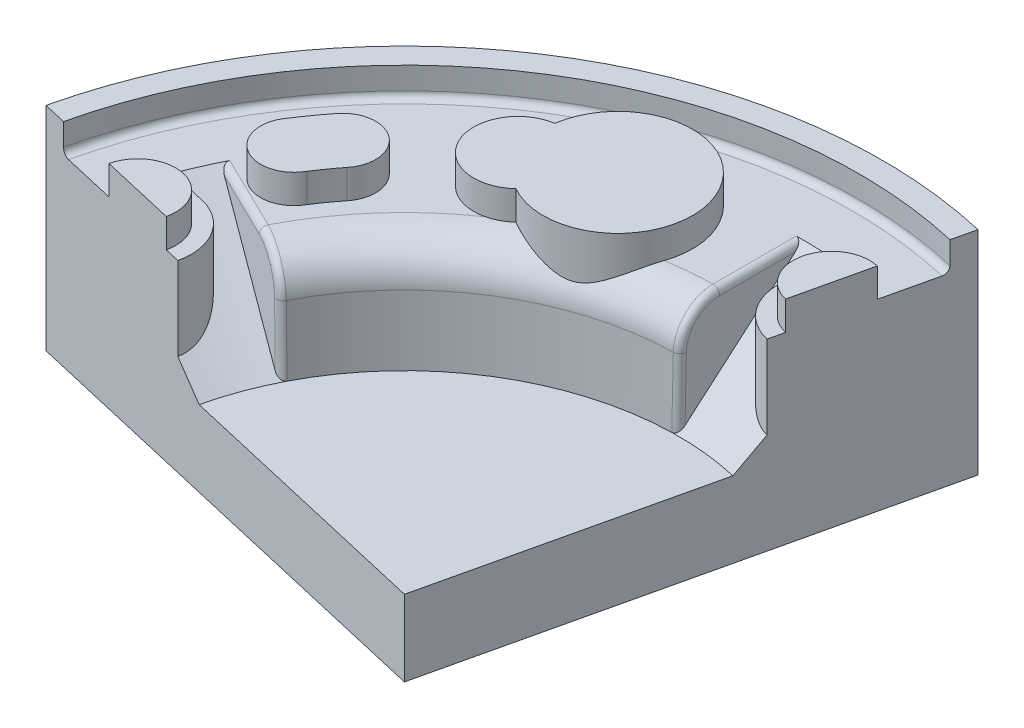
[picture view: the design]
ISO-10303-21;
HEADER;
FILE_DESCRIPTION(('STEP AP214'),'2;1');
FILE_NAME('part.step','',(''),(''),'','','');
FILE_SCHEMA(('AUTOMOTIVE_DESIGN { 1 0 10303 214 1 1 1 1 }'));
ENDSEC;
DATA;
#1=APPLICATION_CONTEXT('core data for automotive mechanical design processes');
#2=APPLICATION_PROTOCOL_DEFINITION('international standard','automotive_design',2000,#1);
#3=PRODUCT_CONTEXT('',#1,'mechanical');
#4=PRODUCT('Part','Part','',(#3));
#5=PRODUCT_RELATED_PRODUCT_CATEGORY('part','',(#4));
#6=PRODUCT_DEFINITION_FORMATION('','',#4);
#7=PRODUCT_DEFINITION_CONTEXT('part definition',#1,'design');
#8=PRODUCT_DEFINITION('design','',#6,#7);
#9=PRODUCT_DEFINITION_SHAPE('','',#8);
#10=(LENGTH_UNIT() NAMED_UNIT(*) SI_UNIT(.MILLI.,.METRE.));
#11=(NAMED_UNIT(*) PLANE_ANGLE_UNIT() SI_UNIT($,.RADIAN.));
#12=(NAMED_UNIT(*) SI_UNIT($,.STERADIAN.) SOLID_ANGLE_UNIT());
#13=UNCERTAINTY_MEASURE_WITH_UNIT(LENGTH_MEASURE(1.E-05),#10,'distance_accuracy_value','');
#14=(GEOMETRIC_REPRESENTATION_CONTEXT(3) GLOBAL_UNCERTAINTY_ASSIGNED_CONTEXT((#13)) GLOBAL_UNIT_ASSIGNED_CONTEXT((#10,
#11,#12)) REPRESENTATION_CONTEXT('',''));
#15=CARTESIAN_POINT('',(0.,0.,0.));
#16=DIRECTION('',(0.,0.,1.));
#17=DIRECTION('',(1.,0.,0.));
#18=AXIS2_PLACEMENT_3D('',#15,#16,#17);
#19=CARTESIAN_POINT('',(121.494829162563,21.9456,16.5481660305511));
#20=DIRECTION('',(0.,-1.,0.));
#21=DIRECTION('',(-0.224951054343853,0.,0.974370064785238));
#22=AXIS2_PLACEMENT_3D('',#19,#20,#21);
#23=PLANE('',#22);
#24=CARTESIAN_POINT('',(22.7978712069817,21.9456,30.2092155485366));
#25=DIRECTION('',(0.,-1.,0.));
#26=DIRECTION('',(0.974370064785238,0.,0.224951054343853));
#27=AXIS2_PLACEMENT_3D('',#24,#25,#26);
#28=CIRCLE('',#27,3.96956319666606);
#29=CARTESIAN_POINT('',(25.8758232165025,21.9456000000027,32.7159351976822));
#30=VERTEX_POINT('',#29);
#31=CARTESIAN_POINT('',(19.6209878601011,21.9456000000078,27.8291222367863));
#32=VERTEX_POINT('',#31);
#33=EDGE_CURVE('E584',#30,#32,#28,.F.);
#34=ORIENTED_EDGE('',*,*,#33,.F.);
#35=CARTESIAN_POINT('',(57.150000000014,21.9456000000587,57.1500000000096));
#36=DIRECTION('',(1.21401796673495E-12,-1.,8.47143766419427E-13));
#37=DIRECTION('',(0.974370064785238,1.37346864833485E-12,0.224951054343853));
#38=AXIS2_PLACEMENT_3D('',#35,#36,#37);
#39=CIRCLE('',#38,39.6874999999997);
#40=CARTESIAN_POINT('',(23.8652618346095,21.9456000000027,35.5346382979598));
#41=VERTEX_POINT('',#40);
#42=EDGE_CURVE('E581',#41,#30,#39,.T.);
#43=ORIENTED_EDGE('',*,*,#42,.F.);
#44=CARTESIAN_POINT('',(20.3938022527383,21.9456,33.5932808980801));
#45=DIRECTION('',(0.,-1.,0.));
#46=DIRECTION('',(-0.224951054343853,0.,0.974370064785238));
#47=AXIS2_PLACEMENT_3D('',#44,#45,#46);
#48=CIRCLE('',#47,3.97742381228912);
#49=CARTESIAN_POINT('',(17.2083142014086,21.9456000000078,31.2115659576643));
#50=VERTEX_POINT('',#49);
#51=EDGE_CURVE('E578',#50,#41,#48,.F.);
#52=ORIENTED_EDGE('',*,*,#51,.F.);
#53=CARTESIAN_POINT('',(57.1499999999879,21.9455999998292,57.1499999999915));
#54=DIRECTION('',(-2.94219527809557E-12,-1.,-2.05842950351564E-12));
#55=DIRECTION('',(0.974370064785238,-3.32983289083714E-12,0.224951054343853));
#56=AXIS2_PLACEMENT_3D('',#53,#54,#55);
#57=CIRCLE('',#56,47.6250000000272);
#58=EDGE_CURVE('E602',#32,#50,#57,.F.);
#59=ORIENTED_EDGE('',*,*,#58,.F.);
#60=EDGE_LOOP('',(#34,#43,#52,#59));
#61=FACE_BOUND('',#60,.T.);
#62=DIRECTION('',(-0.224951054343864,0.,0.974370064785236));
#63=VECTOR('',#62,1.);
#64=CARTESIAN_POINT('',(69.3053761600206,21.9456,4.49928142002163));
#65=LINE('',#64,#63);
#66=CARTESIAN_POINT('',(69.1988846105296,21.9456,4.96054699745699));
#67=VERTEX_POINT('',#66);
#68=CARTESIAN_POINT('',(67.7490188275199,21.9456,11.240605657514));
#69=VERTEX_POINT('',#68);
#70=EDGE_CURVE('E831',#67,#69,#65,.T.);
#71=ORIENTED_EDGE('',*,*,#70,.F.);
#72=CARTESIAN_POINT('',(57.15,21.9456,57.15));
#73=DIRECTION('',(0.,1.,0.));
#74=DIRECTION('',(0.224951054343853,0.,-0.974370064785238));
#75=AXIS2_PLACEMENT_3D('',#72,#73,#74);
#76=CIRCLE('',#75,53.56225);
#77=CARTESIAN_POINT('',(4.96054699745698,21.9456,45.1011153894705));
#78=VERTEX_POINT('',#77);
#79=EDGE_CURVE('E537',#67,#78,#76,.T.);
#80=ORIENTED_EDGE('',*,*,#79,.T.);
#81=DIRECTION('',(-0.974370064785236,0.,-0.224951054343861));
#82=VECTOR('',#81,1.);
#83=CARTESIAN_POINT('',(109.339453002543,21.9456,69.1988846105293));
#84=LINE('',#83,#82);
#85=CARTESIAN_POINT('',(11.240605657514,21.9456,46.5509811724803));
#86=VERTEX_POINT('',#85);
#87=EDGE_CURVE('E858',#86,#78,#84,.T.);
#88=ORIENTED_EDGE('',*,*,#87,.F.);
#89=CARTESIAN_POINT('',(15.695425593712,21.9456,47.5794573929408));
#90=DIRECTION('',(0.,1.,0.));
#91=DIRECTION('',(0.224951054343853,0.,-0.974370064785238));
#92=AXIS2_PLACEMENT_3D('',#89,#90,#91);
#93=CIRCLE('',#92,4.57200000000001);
#94=CARTESIAN_POINT('',(20.1502455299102,21.9456,48.6079336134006));
#95=VERTEX_POINT('',#94);
#96=EDGE_CURVE('E587',#95,#86,#93,.T.);
#97=ORIENTED_EDGE('',*,*,#96,.F.);
#98=CARTESIAN_POINT('',(21.9445480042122,21.9456,49.0221809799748));
#99=VERTEX_POINT('',#98);
#100=EDGE_CURVE('E863',#99,#95,#84,.T.);
#101=ORIENTED_EDGE('',*,*,#100,.F.);
#102=CARTESIAN_POINT('',(15.6954255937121,21.9456,47.5794573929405));
#103=DIRECTION('',(0.,-1.,0.));
#104=DIRECTION('',(-0.224951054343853,0.,0.974370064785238));
#105=AXIS2_PLACEMENT_3D('',#102,#103,#104);
#106=CIRCLE('',#105,6.4135);
#107=CARTESIAN_POINT('',(17.1381491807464,21.9456,41.3303349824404));
#108=VERTEX_POINT('',#107);
#109=EDGE_CURVE('E576',#108,#99,#106,.T.);
#110=ORIENTED_EDGE('',*,*,#109,.F.);
#111=DIRECTION('',(-0.974370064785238,0.,-0.224951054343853));
#112=VECTOR('',#111,1.);
#113=CARTESIAN_POINT('',(110.782176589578,21.9456,62.9497622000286));
#114=LINE('',#113,#112);
#115=CARTESIAN_POINT('',(12.6110488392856,21.9455998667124,40.2851715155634));
#116=VERTEX_POINT('',#115);
#117=EDGE_CURVE('E574',#116,#108,#114,.F.);
#118=ORIENTED_EDGE('',*,*,#117,.F.);
#119=CARTESIAN_POINT('',(57.1499999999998,21.9455997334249,57.15));
#120=DIRECTION('',(0.,1.,0.));
#121=DIRECTION('',(-0.974370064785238,0.,-0.224951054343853));
#122=AXIS2_PLACEMENT_3D('',#119,#120,#121);
#123=CIRCLE('',#122,47.6249996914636);
#124=CARTESIAN_POINT('',(14.6988363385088,21.9455998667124,35.5620562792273));
#125=VERTEX_POINT('',#124);
#126=EDGE_CURVE('E571',#125,#116,#123,.T.);
#127=ORIENTED_EDGE('',*,*,#126,.F.);
#128=DIRECTION('',(-0.898794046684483,0.,-0.438371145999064));
#129=VECTOR('',#128,1.);
#130=CARTESIAN_POINT('',(23.6425655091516,21.9456,39.9242044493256));
#131=LINE('',#130,#129);
#132=CARTESIAN_POINT('',(23.6425655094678,21.9456,39.9242044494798));
#133=VERTEX_POINT('',#132);
#134=EDGE_CURVE('E567',#133,#125,#131,.T.);
#135=ORIENTED_EDGE('',*,*,#134,.F.);
#136=CARTESIAN_POINT('',(57.15,21.9456,57.15));
#137=DIRECTION('',(0.,1.,0.));
#138=DIRECTION('',(0.224951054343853,0.,-0.974370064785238));
#139=AXIS2_PLACEMENT_3D('',#136,#137,#138);
#140=CIRCLE('',#139,37.6759365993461);
#141=CARTESIAN_POINT('',(35.7842299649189,21.9456000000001,26.1180798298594));
#142=VERTEX_POINT('',#141);
#143=EDGE_CURVE('E563',#142,#133,#140,.T.);
#144=ORIENTED_EDGE('',*,*,#143,.F.);
#145=CARTESIAN_POINT('',(34.5456490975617,21.9456,20.9754767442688));
#146=DIRECTION('',(0.,-1.,0.));
#147=DIRECTION('',(-0.224951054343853,0.,0.974370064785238));
#148=AXIS2_PLACEMENT_3D('',#145,#146,#147);
#149=CIRCLE('',#148,5.289654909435);
#150=CARTESIAN_POINT('',(33.7237415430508,21.9456,15.7500660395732));
#151=VERTEX_POINT('',#150);
#152=EDGE_CURVE('E561',#151,#142,#149,.F.);
#153=ORIENTED_EDGE('',*,*,#152,.F.);
#154=CARTESIAN_POINT('',(42.5607112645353,21.9456,17.0662586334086));
#155=DIRECTION('',(0.,1.,0.));
#156=DIRECTION('',(0.224951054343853,0.,-0.974370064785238));
#157=AXIS2_PLACEMENT_3D('',#154,#155,#156);
#158=CIRCLE('',#157,8.93445000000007);
#159=CARTESIAN_POINT('',(51.007334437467,21.9455999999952,19.9781762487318));
#160=VERTEX_POINT('',#159);
#161=EDGE_CURVE('E557',#160,#151,#158,.T.);
#162=ORIENTED_EDGE('',*,*,#161,.F.);
#163=CARTESIAN_POINT('',(57.15,21.9456,57.15));
#164=DIRECTION('',(0.,1.,0.));
#165=DIRECTION('',(0.224951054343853,0.,-0.974370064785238));
#166=AXIS2_PLACEMENT_3D('',#163,#164,#165);
#167=CIRCLE('',#166,37.6759365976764);
#168=CARTESIAN_POINT('',(56.356250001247,21.9456,19.4824256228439));
#169=VERTEX_POINT('',#168);
#170=EDGE_CURVE('E552',#169,#160,#167,.T.);
#171=ORIENTED_EDGE('',*,*,#170,.F.);
#172=DIRECTION('',(-8.78967121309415E-10,0.,1.));
#173=VECTOR('',#172,1.);
#174=CARTESIAN_POINT('',(56.3562500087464,21.9456,9.53161667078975));
#175=LINE('',#174,#173);
#176=CARTESIAN_POINT('',(56.35624999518,21.9456000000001,9.53161504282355));
#177=VERTEX_POINT('',#176);
#178=EDGE_CURVE('E548',#177,#169,#175,.T.);
#179=ORIENTED_EDGE('',*,*,#178,.F.);
#180=CARTESIAN_POINT('',(57.1500000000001,21.9456000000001,57.1499999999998));
#181=DIRECTION('',(0.,1.,0.));
#182=DIRECTION('',(0.224951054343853,0.,-0.974370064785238));
#183=AXIS2_PLACEMENT_3D('',#180,#181,#182);
#184=CIRCLE('',#183,47.6249999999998);
#185=CARTESIAN_POINT('',(61.5165836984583,21.9456000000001,9.72560151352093));
#186=VERTEX_POINT('',#185);
#187=EDGE_CURVE('E545',#186,#177,#184,.T.);
#188=ORIENTED_EDGE('',*,*,#187,.F.);
#189=DIRECTION('',(-0.224951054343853,0.,0.974370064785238));
#190=VECTOR('',#189,1.);
#191=CARTESIAN_POINT('',(63.0562537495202,21.9456,3.05655783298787));
#192=LINE('',#191,#190);
#193=CARTESIAN_POINT('',(60.4714201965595,21.9456,14.2527020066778));
#194=VERTEX_POINT('',#193);
#195=EDGE_CURVE('E542',#194,#186,#192,.F.);
#196=ORIENTED_EDGE('',*,*,#195,.F.);
#197=CARTESIAN_POINT('',(66.7205426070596,21.9456,15.6954255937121));
#198=DIRECTION('',(0.,-1.,0.));
#199=DIRECTION('',(0.974370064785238,0.,0.224951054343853));
#200=AXIS2_PLACEMENT_3D('',#197,#198,#199);
#201=CIRCLE('',#200,6.4135);
#202=CARTESIAN_POINT('',(65.2778190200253,21.9456,21.9445480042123));
#203=VERTEX_POINT('',#202);
#204=EDGE_CURVE('E540',#203,#194,#201,.T.);
#205=ORIENTED_EDGE('',*,*,#204,.F.);
#206=CARTESIAN_POINT('',(65.6920663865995,21.9456,20.1502455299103));
#207=VERTEX_POINT('',#206);
#208=EDGE_CURVE('E834',#207,#203,#65,.T.);
#209=ORIENTED_EDGE('',*,*,#208,.F.);
#210=CARTESIAN_POINT('',(66.7205426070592,21.9456,15.695425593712));
#211=DIRECTION('',(0.,1.,0.));
#212=DIRECTION('',(-0.974370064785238,0.,-0.224951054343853));
#213=AXIS2_PLACEMENT_3D('',#210,#211,#212);
#214=CIRCLE('',#213,4.57200000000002);
#215=EDGE_CURVE('E590',#69,#207,#214,.T.);
#216=ORIENTED_EDGE('',*,*,#215,.F.);
#217=EDGE_LOOP('',(#71,#80,#88,#97,#101,#110,#118,#127,#135,#144,#153,#162,#171,#179,#188,#196,
#205,#209,#216));
#218=FACE_BOUND('',#217,.T.);
#219=ADVANCED_FACE('F40',(#61,#218),#23,.F.);
#220=CARTESIAN_POINT('',(66.7205426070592,21.9456,15.695425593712));
#221=DIRECTION('',(0.,1.,0.));
#222=DIRECTION('',(-0.974370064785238,0.,-0.224951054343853));
#223=AXIS2_PLACEMENT_3D('',#220,#221,#222);
#224=CYLINDRICAL_SURFACE('',#223,4.57200000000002);
#225=CARTESIAN_POINT('',(66.7205426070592,25.4,15.695425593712));
#226=DIRECTION('',(0.,1.,0.));
#227=DIRECTION('',(-0.974370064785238,0.,-0.224951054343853));
#228=AXIS2_PLACEMENT_3D('',#225,#226,#227);
#229=CIRCLE('',#228,4.57200000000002);
#230=CARTESIAN_POINT('',(65.6920663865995,25.4,20.1502455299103));
#231=VERTEX_POINT('',#230);
#232=CARTESIAN_POINT('',(67.7490188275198,25.4,11.240605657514));
#233=VERTEX_POINT('',#232);
#234=EDGE_CURVE('E534',#231,#233,#229,.F.);
#235=ORIENTED_EDGE('',*,*,#234,.T.);
#236=DIRECTION('',(0.,1.,0.));
#237=VECTOR('',#236,1.);
#238=CARTESIAN_POINT('',(67.7490188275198,21.9456,11.240605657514));
#239=LINE('',#238,#237);
#240=EDGE_CURVE('E833',#233,#69,#239,.F.);
#241=ORIENTED_EDGE('',*,*,#240,.T.);
#242=ORIENTED_EDGE('',*,*,#215,.T.);
#243=DIRECTION('',(0.,1.,0.));
#244=VECTOR('',#243,1.);
#245=CARTESIAN_POINT('',(65.6920663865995,21.9456,20.1502455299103));
#246=LINE('',#245,#244);
#247=EDGE_CURVE('E839',#207,#231,#246,.T.);
#248=ORIENTED_EDGE('',*,*,#247,.T.);
#249=EDGE_LOOP('',(#235,#241,#242,#248));
#250=FACE_BOUND('',#249,.T.);
#251=ADVANCED_FACE('F646',(#250),#224,.T.);
#252=CARTESIAN_POINT('',(57.15,25.4,57.15));
#253=DIRECTION('',(0.,-1.,0.));
#254=DIRECTION('',(-0.224951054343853,0.,0.974370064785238));
#255=AXIS2_PLACEMENT_3D('',#252,#253,#254);
#256=PLANE('',#255);
#257=DIRECTION('',(-0.224951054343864,0.,0.974370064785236));
#258=VECTOR('',#257,1.);
#259=CARTESIAN_POINT('',(57.15,25.4,57.15));
#260=LINE('',#259,#258);
#261=EDGE_CURVE('E837',#233,#231,#260,.T.);
#262=ORIENTED_EDGE('',*,*,#261,.F.);
#263=ORIENTED_EDGE('',*,*,#234,.F.);
#264=EDGE_LOOP('',(#262,#263));
#265=FACE_BOUND('',#264,.T.);
#266=ADVANCED_FACE('F652',(#265),#256,.F.);
#267=CARTESIAN_POINT('',(15.695425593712,21.9456,47.5794573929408));
#268=DIRECTION('',(0.,1.,0.));
#269=DIRECTION('',(0.224951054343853,0.,-0.974370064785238));
#270=AXIS2_PLACEMENT_3D('',#267,#268,#269);
#271=CYLINDRICAL_SURFACE('',#270,4.57200000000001);
#272=CARTESIAN_POINT('',(15.695425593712,25.4,47.5794573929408));
#273=DIRECTION('',(0.,1.,0.));
#274=DIRECTION('',(0.224951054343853,0.,-0.974370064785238));
#275=AXIS2_PLACEMENT_3D('',#272,#273,#274);
#276=CIRCLE('',#275,4.57200000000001);
#277=CARTESIAN_POINT('',(11.240605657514,25.4,46.5509811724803));
#278=VERTEX_POINT('',#277);
#279=CARTESIAN_POINT('',(20.1502455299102,25.4,48.6079336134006));
#280=VERTEX_POINT('',#279);
#281=EDGE_CURVE('E531',#278,#280,#276,.F.);
#282=ORIENTED_EDGE('',*,*,#281,.T.);
#283=DIRECTION('',(0.,1.,0.));
#284=VECTOR('',#283,1.);
#285=CARTESIAN_POINT('',(20.1502455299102,21.9456,48.6079336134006));
#286=LINE('',#285,#284);
#287=EDGE_CURVE('E872',#280,#95,#286,.F.);
#288=ORIENTED_EDGE('',*,*,#287,.T.);
#289=ORIENTED_EDGE('',*,*,#96,.T.);
#290=DIRECTION('',(0.,1.,0.));
#291=VECTOR('',#290,1.);
#292=CARTESIAN_POINT('',(11.240605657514,21.9456,46.5509811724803));
#293=LINE('',#292,#291);
#294=EDGE_CURVE('E861',#86,#278,#293,.T.);
#295=ORIENTED_EDGE('',*,*,#294,.T.);
#296=EDGE_LOOP('',(#282,#288,#289,#295));
#297=FACE_BOUND('',#296,.T.);
#298=ADVANCED_FACE('F662',(#297),#271,.T.);
#299=CARTESIAN_POINT('',(57.15,25.4,57.15));
#300=DIRECTION('',(0.,-1.,0.));
#301=DIRECTION('',(-0.224951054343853,0.,0.974370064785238));
#302=AXIS2_PLACEMENT_3D('',#299,#300,#301);
#303=PLANE('',#302);
#304=DIRECTION('',(-0.974370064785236,0.,-0.224951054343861));
#305=VECTOR('',#304,1.);
#306=CARTESIAN_POINT('',(57.15,25.4,57.15));
#307=LINE('',#306,#305);
#308=EDGE_CURVE('E870',#280,#278,#307,.T.);
#309=ORIENTED_EDGE('',*,*,#308,.F.);
#310=ORIENTED_EDGE('',*,*,#281,.F.);
#311=EDGE_LOOP('',(#309,#310));
#312=FACE_BOUND('',#311,.T.);
#313=ADVANCED_FACE('F463',(#312),#303,.F.);
#314=CARTESIAN_POINT('',(57.1499999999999,9.07521658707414,57.15));
#315=DIRECTION('',(0.,1.,0.));
#316=DIRECTION('',(-0.974370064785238,0.,-0.224951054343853));
#317=AXIS2_PLACEMENT_3D('',#314,#315,#316);
#318=CONICAL_SURFACE('',#317,32.7287229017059,0.858230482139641);
#319=DIRECTION('',(0.737293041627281,-0.653777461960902,0.170217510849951));
#320=VECTOR('',#319,1.);
#321=CARTESIAN_POINT('',(57.15,-19.2024000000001,57.15));
#322=LINE('',#321,#320);
#323=CARTESIAN_POINT('',(25.260112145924,9.07521658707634,49.7876392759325));
#324=VERTEX_POINT('',#323);
#325=CARTESIAN_POINT('',(21.9445480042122,12.015216,49.0221809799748));
#326=VERTEX_POINT('',#325);
#327=EDGE_CURVE('E817',#324,#326,#322,.F.);
#328=ORIENTED_EDGE('',*,*,#327,.F.);
#329=CARTESIAN_POINT('',(57.1499999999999,9.07521658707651,57.15));
#330=DIRECTION('',(0.,1.,0.));
#331=DIRECTION('',(-0.974370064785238,0.,-0.224951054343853));
#332=AXIS2_PLACEMENT_3D('',#329,#330,#331);
#333=CIRCLE('',#332,32.7287229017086);
#334=CARTESIAN_POINT('',(28.0815863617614,9.07521658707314,42.1101651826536));
#335=VERTEX_POINT('',#334);
#336=EDGE_CURVE('E508',#335,#324,#333,.T.);
#337=ORIENTED_EDGE('',*,*,#336,.F.);
#338=CARTESIAN_POINT('',(28.08158636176,9.07521658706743,42.1101651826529));
#339=CARTESIAN_POINT('',(28.0732919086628,9.0752203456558,42.1261867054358));
#340=CARTESIAN_POINT('',(28.0644082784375,9.07581936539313,42.1418806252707));
#341=CARTESIAN_POINT('',(28.0456034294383,9.07813604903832,42.1725197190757));
#342=CARTESIAN_POINT('',(28.0356836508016,9.07985217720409,42.1874658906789));
#343=CARTESIAN_POINT('',(28.0047099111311,9.08653548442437,42.230874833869));
#344=CARTESIAN_POINT('',(27.9823048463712,9.09304004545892,42.2581661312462));
#345=CARTESIAN_POINT('',(27.9348211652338,9.10975582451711,42.3087714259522));
#346=CARTESIAN_POINT('',(27.909751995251,9.11995423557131,42.3320987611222));
#347=CARTESIAN_POINT('',(27.8577706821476,9.14335231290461,42.3748925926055));
#348=CARTESIAN_POINT('',(27.8308562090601,9.15655582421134,42.3943540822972));
#349=CARTESIAN_POINT('',(27.7655185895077,9.19093595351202,42.4357898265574));
#350=CARTESIAN_POINT('',(27.726553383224,9.21324821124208,42.455985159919));
#351=CARTESIAN_POINT('',(27.667521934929,9.2492928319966,42.4809228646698));
#352=CARTESIAN_POINT('',(27.6477280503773,9.26175040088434,42.4883474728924));
#353=CARTESIAN_POINT('',(27.608040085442,9.28743259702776,42.5014459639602));
#354=CARTESIAN_POINT('',(27.5881459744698,9.30065747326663,42.5071192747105));
#355=CARTESIAN_POINT('',(27.5414675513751,9.33245183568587,42.5184775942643));
#356=CARTESIAN_POINT('',(27.5146938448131,9.35128013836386,42.5234801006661));
#357=CARTESIAN_POINT('',(27.4614015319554,9.38979571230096,42.5307653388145));
#358=CARTESIAN_POINT('',(27.4348830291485,9.40948331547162,42.5330470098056));
#359=CARTESIAN_POINT('',(27.355846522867,9.46960775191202,42.5360966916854));
#360=CARTESIAN_POINT('',(27.3039161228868,9.51105894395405,42.5330539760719));
#361=CARTESIAN_POINT('',(27.2112038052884,9.58824752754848,42.5192708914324));
#362=CARTESIAN_POINT('',(27.1700178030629,9.62377078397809,42.5099139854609));
#363=CARTESIAN_POINT('',(27.0902389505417,9.69505703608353,42.4852652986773));
#364=CARTESIAN_POINT('',(27.0516295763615,9.73081646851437,42.4700166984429));
#365=CARTESIAN_POINT('',(27.0143982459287,9.76659464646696,42.4518849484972));
#366=B_SPLINE_CURVE_WITH_KNOTS('',3,(#338,#339,#340,#341,#342,#343,#344,#345,#346,#347,#348,
#349,#350,#351,#352,#353,#354,#355,#356,#357,#358,#359,#360,#361,#362,#363,#364,#365),
.UNSPECIFIED.,.F.,.F.,(4,2,2,2,2,2,2,2,2,2,2,2,2,4),(0.,0.0540670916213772,0.108060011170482,
0.215182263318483,0.321936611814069,0.428828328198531,0.575666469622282,0.649228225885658,
0.722813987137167,0.821998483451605,0.921221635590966,1.1199190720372,1.28513555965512,
1.44916345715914),.UNSPECIFIED.);
#367=CARTESIAN_POINT('',(27.0143982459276,9.7665946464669,42.4518849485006));
#368=VERTEX_POINT('',#367);
#369=EDGE_CURVE('E275',#335,#368,#366,.T.);
#370=ORIENTED_EDGE('',*,*,#369,.T.);
#371=DIRECTION('',(0.680105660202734,-0.653777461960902,0.331709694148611));
#372=VECTOR('',#371,1.);
#373=CARTESIAN_POINT('',(21.0392761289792,15.510408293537,39.5376231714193));
#374=LINE('',#373,#372);
#375=CARTESIAN_POINT('',(15.1706485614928,21.15185,36.6753022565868));
#376=VERTEX_POINT('',#375);
#377=EDGE_CURVE('E115',#376,#368,#374,.T.);
#378=ORIENTED_EDGE('',*,*,#377,.F.);
#379=CARTESIAN_POINT('',(14.6988362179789,21.9456000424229,35.5620562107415));
#380=CARTESIAN_POINT('',(14.6912120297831,21.9456027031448,35.5770415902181));
#381=CARTESIAN_POINT('',(14.6841578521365,21.945065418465,35.5923047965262));
#382=CARTESIAN_POINT('',(14.6712316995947,21.9429368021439,35.623236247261));
#383=CARTESIAN_POINT('',(14.6653586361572,21.9413464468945,35.6389041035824));
#384=CARTESIAN_POINT('',(14.6496692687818,21.9350787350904,35.6859877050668));
#385=CARTESIAN_POINT('',(14.641615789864,21.9289034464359,35.7178152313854));
#386=CARTESIAN_POINT('',(14.6301719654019,21.9130841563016,35.7812710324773));
#387=CARTESIAN_POINT('',(14.6267662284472,21.9034517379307,35.8128996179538));
#388=CARTESIAN_POINT('',(14.6240904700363,21.8813368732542,35.8753806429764));
#389=CARTESIAN_POINT('',(14.6248315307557,21.8688468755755,35.9062307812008));
#390=CARTESIAN_POINT('',(14.6310928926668,21.8352787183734,35.9807118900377));
#391=CARTESIAN_POINT('',(14.638683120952,21.8129135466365,36.0235848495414));
#392=CARTESIAN_POINT('',(14.6599132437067,21.7649032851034,36.1058234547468));
#393=CARTESIAN_POINT('',(14.6735650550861,21.7392518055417,36.1451820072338));
#394=CARTESIAN_POINT('',(14.7135158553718,21.6724978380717,36.2387751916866));
#395=CARTESIAN_POINT('',(14.7427316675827,21.6300146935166,36.2907725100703));
#396=CARTESIAN_POINT('',(14.8088245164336,21.542139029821,36.386917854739));
#397=CARTESIAN_POINT('',(14.8457250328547,21.4967378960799,36.4310410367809));
#398=CARTESIAN_POINT('',(14.9276820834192,21.4016382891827,36.5139813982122));
#399=CARTESIAN_POINT('',(14.9730875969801,21.3518433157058,36.5523422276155));
#400=CARTESIAN_POINT('',(15.0447972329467,21.2768305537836,36.6033581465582));
#401=CARTESIAN_POINT('',(15.0691823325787,21.2518864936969,36.6192186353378));
#402=CARTESIAN_POINT('',(15.1190874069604,21.2019141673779,36.6488365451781));
#403=CARTESIAN_POINT('',(15.1446068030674,21.1768859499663,36.6625950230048));
#404=CARTESIAN_POINT('',(15.170648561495,21.15185,36.6753022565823));
#405=B_SPLINE_CURVE_WITH_KNOTS('',3,(#379,#380,#381,#382,#383,#384,#385,#386,#387,#388,#389,
#390,#391,#392,#393,#394,#395,#396,#397,#398,#399,#400,#401,#402,#403,#404),.UNSPECIFIED.,.F.,
.F.,(4,2,2,2,2,2,2,2,2,2,2,2,4),(0.,0.0503993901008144,0.100752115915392,0.20036197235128,
0.299641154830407,0.399185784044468,0.545208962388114,0.691520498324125,0.909995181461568,
1.12914745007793,1.36101415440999,1.4759123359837,1.59075256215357),.UNSPECIFIED.);
#406=EDGE_CURVE('E161',#125,#376,#405,.T.);
#407=ORIENTED_EDGE('',*,*,#406,.F.);
#408=ORIENTED_EDGE('',*,*,#126,.T.);
#409=CARTESIAN_POINT('',(17.1381491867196,17.9717962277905,41.3303349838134));
#410=CARTESIAN_POINT('',(16.3833011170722,18.6336992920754,41.1560645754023));
#411=CARTESIAN_POINT('',(15.6286187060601,19.2958011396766,40.9818324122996));
#412=CARTESIAN_POINT('',(14.1195852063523,20.6204023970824,40.6334445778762));
#413=CARTESIAN_POINT('',(13.3652341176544,21.2829018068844,40.4592889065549));
#414=CARTESIAN_POINT('',(12.6110486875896,21.9456,40.2851714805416));
#415=B_SPLINE_CURVE_WITH_KNOTS('',3,(#409,#410,#411,#412,#413,#414),.UNSPECIFIED.,.F.,.F.,(4,2,
4),(0.,3.05688259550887,6.1137651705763),.UNSPECIFIED.);
#416=CARTESIAN_POINT('',(17.1381298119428,17.9717863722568,41.3303814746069));
#417=VERTEX_POINT('',#416);
#418=EDGE_CURVE('E482',#417,#116,#415,.T.);
#419=ORIENTED_EDGE('',*,*,#418,.F.);
#420=CARTESIAN_POINT('',(14.2527043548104,17.9717929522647,53.8285812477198));
#421=CARTESIAN_POINT('',(14.4523727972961,17.7967339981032,53.8746546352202));
#422=CARTESIAN_POINT('',(14.6536271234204,17.6209578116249,53.9110609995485));
#423=CARTESIAN_POINT('',(15.058245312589,17.2688690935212,53.9644948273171));
#424=CARTESIAN_POINT('',(15.2616092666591,17.0925565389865,53.9815214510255));
#425=CARTESIAN_POINT('',(15.6717078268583,16.738286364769,53.9962309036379));
#426=CARTESIAN_POINT('',(15.8784543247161,16.5603330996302,53.9936893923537));
#427=CARTESIAN_POINT('',(16.2919387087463,16.205814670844,53.968515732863));
#428=CARTESIAN_POINT('',(16.4986765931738,16.0292496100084,53.9458821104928));
#429=CARTESIAN_POINT('',(16.9426127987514,15.651787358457,53.8751278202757));
#430=CARTESIAN_POINT('',(17.1796337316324,15.4512990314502,53.8236384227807));
#431=CARTESIAN_POINT('',(17.6504842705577,15.0555877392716,53.6925969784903));
#432=CARTESIAN_POINT('',(17.8843127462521,14.860366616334,53.6130352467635));
#433=CARTESIAN_POINT('',(18.3456003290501,14.4785683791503,53.4250802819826));
#434=CARTESIAN_POINT('',(18.5730830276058,14.291956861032,53.3168160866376));
#435=CARTESIAN_POINT('',(19.0199682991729,13.9297741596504,53.0699498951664));
#436=CARTESIAN_POINT('',(19.2393779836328,13.7541931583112,52.9313753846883));
#437=CARTESIAN_POINT('',(19.6925085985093,13.3979149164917,52.6037476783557));
#438=CARTESIAN_POINT('',(19.9248292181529,13.2190916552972,52.4106515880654));
#439=CARTESIAN_POINT('',(20.368788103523,12.8879784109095,51.9825842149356));
#440=CARTESIAN_POINT('',(20.5804560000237,12.7356501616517,51.7476743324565));
#441=CARTESIAN_POINT('',(20.9386487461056,12.491662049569,51.28232359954));
#442=CARTESIAN_POINT('',(21.0900181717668,12.3940061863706,51.0588517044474));
#443=CARTESIAN_POINT('',(21.2977316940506,12.2703688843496,50.7045120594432));
#444=CARTESIAN_POINT('',(21.3637604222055,12.2329575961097,50.5831769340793));
#445=CARTESIAN_POINT('',(21.4886111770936,12.1664565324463,50.33468557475));
#446=CARTESIAN_POINT('',(21.5474364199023,12.1373630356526,50.2075319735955));
#447=CARTESIAN_POINT('',(21.6575451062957,12.0879453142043,49.9472065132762));
#448=CARTESIAN_POINT('',(21.7087702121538,12.0676868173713,49.8139974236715));
#449=CARTESIAN_POINT('',(21.8024883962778,12.036739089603,49.5434472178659));
#450=CARTESIAN_POINT('',(21.8449814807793,12.0260498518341,49.4061061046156));
#451=CARTESIAN_POINT('',(21.9206977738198,12.0145180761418,49.1285396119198));
#452=CARTESIAN_POINT('',(21.9539244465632,12.0136718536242,48.98831533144));
#453=CARTESIAN_POINT('',(22.0108085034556,12.0218397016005,48.7062308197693));
#454=CARTESIAN_POINT('',(22.0344665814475,12.030853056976,48.5643707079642));
#455=CARTESIAN_POINT('',(22.0700102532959,12.056948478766,48.2962808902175));
#456=CARTESIAN_POINT('',(22.0829193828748,12.0730110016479,48.1700845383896));
#457=CARTESIAN_POINT('',(22.1012161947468,12.1124120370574,47.9182405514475));
#458=CARTESIAN_POINT('',(22.1066011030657,12.1357532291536,47.7925931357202));
#459=CARTESIAN_POINT('',(22.1100377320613,12.1892895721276,47.5426741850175));
#460=CARTESIAN_POINT('',(22.108089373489,12.2194847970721,47.4184026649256));
#461=CARTESIAN_POINT('',(22.0971519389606,12.2862356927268,47.1718868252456));
#462=CARTESIAN_POINT('',(22.0881614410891,12.3227926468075,47.0496429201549));
#463=CARTESIAN_POINT('',(22.0596826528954,12.4139068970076,46.770444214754));
#464=CARTESIAN_POINT('',(22.0378129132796,12.4705394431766,46.6144032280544));
#465=CARTESIAN_POINT('',(21.9835015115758,12.5925511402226,46.3076996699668));
#466=CARTESIAN_POINT('',(21.9510571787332,12.6579324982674,46.1570384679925));
#467=CARTESIAN_POINT('',(21.839133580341,12.8655857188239,45.7137866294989));
#468=CARTESIAN_POINT('',(21.7450881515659,13.0192930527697,45.4301456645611));
#469=CARTESIAN_POINT('',(21.4856534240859,13.4076852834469,44.7931945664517));
#470=CARTESIAN_POINT('',(21.3067811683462,13.6516948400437,44.4511368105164));
#471=CARTESIAN_POINT('',(21.0043299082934,14.0368725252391,43.9761456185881));
#472=CARTESIAN_POINT('',(20.8976612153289,14.1686429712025,43.823991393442));
#473=CARTESIAN_POINT('',(20.6740599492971,14.4373689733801,43.5322433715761));
#474=CARTESIAN_POINT('',(20.5571274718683,14.5743244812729,43.3926494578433));
#475=CARTESIAN_POINT('',(20.2777879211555,14.8937677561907,43.0861444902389));
#476=CARTESIAN_POINT('',(20.1122338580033,15.0776316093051,42.9235363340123));
#477=CARTESIAN_POINT('',(19.7676235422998,15.4501032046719,42.6193136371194));
#478=CARTESIAN_POINT('',(19.5885623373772,15.6387126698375,42.4777068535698));
#479=CARTESIAN_POINT('',(19.2187628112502,16.0188280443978,42.2156528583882));
#480=CARTESIAN_POINT('',(19.0280321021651,16.2103320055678,42.0951920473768));
#481=CARTESIAN_POINT('',(18.6363236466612,16.5948521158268,41.8755562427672));
#482=CARTESIAN_POINT('',(18.4353504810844,16.7878675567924,41.7763718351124));
#483=CARTESIAN_POINT('',(18.0537339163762,17.1466577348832,41.6122005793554));
#484=CARTESIAN_POINT('',(17.8742768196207,17.3123931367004,41.54435427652));
#485=CARTESIAN_POINT('',(17.5100788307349,17.6428908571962,41.425062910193));
#486=CARTESIAN_POINT('',(17.3253538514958,17.8076545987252,41.3735731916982));
#487=CARTESIAN_POINT('',(17.138149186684,17.9717962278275,41.3303349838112));
#488=B_SPLINE_CURVE_WITH_KNOTS('',3,(#420,#421,#422,#423,#424,#425,#426,#427,#428,#429,#430,
#431,#432,#433,#434,#435,#436,#437,#438,#439,#440,#441,#442,#443,#444,#445,#446,#447,#448,#449,
#450,#451,#452,#453,#454,#455,#456,#457,#458,#459,#460,#461,#462,#463,#464,#465,#466,#467,#468,
#469,#470,#471,#472,#473,#474,#475,#476,#477,#478,#479,#480,#481,#482,#483,#484,#485,#486,#487),
.UNSPECIFIED.,.F.,.F.,(4,2,2,2,2,2,2,2,2,2,2,2,2,2,2,2,2,2,2,2,2,2,2,2,2,2,2,2,2,2,2,2,2,4),(0.,
0.808334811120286,1.61670464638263,2.43435577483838,3.2520668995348,4.1948456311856,
5.1379499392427,6.07688418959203,7.01497051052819,8.06459720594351,9.1126951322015,
9.97002417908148,10.3989067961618,10.8275972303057,11.2594246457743,11.6912517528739,
12.1229172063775,12.5545513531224,12.937723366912,13.3210366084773,13.704353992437,
14.0877487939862,14.5893068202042,15.0909916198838,16.0950461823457,17.457355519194,
18.14028978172,18.8232176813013,19.7102301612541,20.5975694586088,21.4843359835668,
22.3707093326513,23.1307197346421,23.8886370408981),.UNSPECIFIED.);
#489=EDGE_CURVE('E47',#326,#417,#488,.T.);
#490=ORIENTED_EDGE('',*,*,#489,.F.);
#491=EDGE_LOOP('',(#328,#337,#370,#378,#407,#408,#419,#490));
#492=FACE_BOUND('',#491,.T.);
#493=ADVANCED_FACE('F459',(#492),#318,.F.);
#494=CARTESIAN_POINT('',(15.6954255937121,21.9456,47.5794573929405));
#495=DIRECTION('',(0.,-1.,0.));
#496=DIRECTION('',(-0.224951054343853,0.,0.974370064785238));
#497=AXIS2_PLACEMENT_3D('',#494,#495,#496);
#498=CYLINDRICAL_SURFACE('',#497,6.4135);
#499=ORIENTED_EDGE('',*,*,#109,.T.);
#500=DIRECTION('',(0.,-1.,0.));
#501=VECTOR('',#500,1.);
#502=CARTESIAN_POINT('',(21.9445480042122,21.9456,49.0221809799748));
#503=LINE('',#502,#501);
#504=EDGE_CURVE('E822',#99,#326,#503,.T.);
#505=ORIENTED_EDGE('',*,*,#504,.T.);
#506=ORIENTED_EDGE('',*,*,#489,.T.);
#507=CARTESIAN_POINT('',(17.1381369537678,17.9717815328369,41.3303321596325));
#508=CARTESIAN_POINT('',(17.1381374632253,18.137357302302,41.330332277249));
#509=CARTESIAN_POINT('',(17.1381379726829,18.3029330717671,41.3303323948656));
#510=CARTESIAN_POINT('',(17.1381389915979,18.6340846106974,41.3303326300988));
#511=CARTESIAN_POINT('',(17.1381395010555,18.7996603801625,41.3303327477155));
#512=CARTESIAN_POINT('',(17.1381405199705,19.1308119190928,41.330332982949));
#513=CARTESIAN_POINT('',(17.1381410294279,19.2963876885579,41.3303331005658));
#514=CARTESIAN_POINT('',(17.1381420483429,19.6275392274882,41.3303333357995));
#515=CARTESIAN_POINT('',(17.1381425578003,19.7931149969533,41.3303334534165));
#516=CARTESIAN_POINT('',(17.1381435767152,20.1242665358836,41.3303336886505));
#517=CARTESIAN_POINT('',(17.1381440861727,20.2898423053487,41.3303338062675));
#518=CARTESIAN_POINT('',(17.1381451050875,20.620993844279,41.3303340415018));
#519=CARTESIAN_POINT('',(17.1381456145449,20.7865696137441,41.3303341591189));
#520=CARTESIAN_POINT('',(17.1381466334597,21.1177211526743,41.3303343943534));
#521=CARTESIAN_POINT('',(17.138147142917,21.2832969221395,41.3303345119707));
#522=CARTESIAN_POINT('',(17.1381481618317,21.6144484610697,41.3303347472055));
#523=CARTESIAN_POINT('',(17.1381486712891,21.7800242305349,41.3303348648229));
#524=CARTESIAN_POINT('',(17.1381491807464,21.9456,41.3303349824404));
#525=B_SPLINE_CURVE_WITH_KNOTS('',3,(#507,#508,#509,#510,#511,#512,#513,#514,#515,#516,#517,
#518,#519,#520,#521,#522,#523,#524),.UNSPECIFIED.,.F.,.F.,(4,2,2,2,2,2,2,2,4),(0.,
0.496727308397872,0.99345461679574,1.49018192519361,1.98690923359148,2.48363654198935,
2.98036385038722,3.47709115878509,3.97381846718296),.UNSPECIFIED.);
#526=EDGE_CURVE('E488',#417,#108,#525,.T.);
#527=ORIENTED_EDGE('',*,*,#526,.T.);
#528=EDGE_LOOP('',(#499,#505,#506,#527));
#529=FACE_BOUND('',#528,.T.);
#530=ADVANCED_FACE('F283',(#529),#498,.T.);
#531=CARTESIAN_POINT('',(57.15,9.0752165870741,57.1499999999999));
#532=DIRECTION('',(0.,1.,0.));
#533=DIRECTION('',(0.224951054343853,0.,-0.974370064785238));
#534=AXIS2_PLACEMENT_3D('',#531,#532,#533);
#535=CONICAL_SURFACE('',#534,32.7287229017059,0.858230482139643);
#536=DIRECTION('',(0.170217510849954,0.653777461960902,-0.737293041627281));
#537=VECTOR('',#536,1.);
#538=CARTESIAN_POINT('',(57.15,-19.2024,57.15));
#539=LINE('',#538,#537);
#540=CARTESIAN_POINT('',(65.2778190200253,12.015216,21.9445480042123));
#541=VERTEX_POINT('',#540);
#542=CARTESIAN_POINT('',(64.5123607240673,9.07521658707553,25.2601121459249));
#543=VERTEX_POINT('',#542);
#544=EDGE_CURVE('E811',#541,#543,#539,.F.);
#545=ORIENTED_EDGE('',*,*,#544,.F.);
#546=CARTESIAN_POINT('',(60.4714187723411,17.9717926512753,14.2527049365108));
#547=CARTESIAN_POINT('',(60.4253453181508,17.7967336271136,14.4523733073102));
#548=CARTESIAN_POINT('',(60.3889389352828,17.6209574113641,14.6536276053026));
#549=CARTESIAN_POINT('',(60.3355051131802,17.2688686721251,15.0582457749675));
#550=CARTESIAN_POINT('',(60.3184785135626,17.0925561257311,15.2616097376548));
#551=CARTESIAN_POINT('',(60.3037690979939,16.7382859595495,15.6717083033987));
#552=CARTESIAN_POINT('',(60.306310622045,16.5603326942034,15.8784547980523));
#553=CARTESIAN_POINT('',(60.3314843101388,16.2058142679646,16.2919391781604));
#554=CARTESIAN_POINT('',(60.3541179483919,16.0292492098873,16.49867706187));
#555=CARTESIAN_POINT('',(60.4248722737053,15.6517869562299,16.9426132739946));
#556=CARTESIAN_POINT('',(60.4763616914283,15.4512986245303,17.1796342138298));
#557=CARTESIAN_POINT('',(60.6074031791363,15.0555873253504,17.6504847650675));
#558=CARTESIAN_POINT('',(60.6869649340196,14.8603662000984,17.8843132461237));
#559=CARTESIAN_POINT('',(60.8749199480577,14.4785679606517,18.3456008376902));
#560=CARTESIAN_POINT('',(60.9831841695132,14.2919564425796,18.5730835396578));
#561=CARTESIAN_POINT('',(61.2300504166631,13.9297737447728,19.0199688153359));
#562=CARTESIAN_POINT('',(61.3686249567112,13.7541927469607,19.239378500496));
#563=CARTESIAN_POINT('',(61.6962527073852,13.3979145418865,19.6925090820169));
#564=CARTESIAN_POINT('',(61.8893488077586,13.2190913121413,19.9248296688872));
#565=CARTESIAN_POINT('',(62.317416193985,12.8879781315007,20.3687884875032));
#566=CARTESIAN_POINT('',(62.5523260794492,12.7356499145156,20.5804563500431));
#567=CARTESIAN_POINT('',(63.0176768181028,12.4916618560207,20.9386490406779));
#568=CARTESIAN_POINT('',(63.2411487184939,12.3940060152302,21.0900184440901));
#569=CARTESIAN_POINT('',(63.5954883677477,12.2703687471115,21.2977319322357));
#570=CARTESIAN_POINT('',(63.7168234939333,12.2329574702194,21.3637606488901));
#571=CARTESIAN_POINT('',(63.9653148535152,12.1664564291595,21.4886113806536));
#572=CARTESIAN_POINT('',(64.0924684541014,12.1373629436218,21.5474366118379));
#573=CARTESIAN_POINT('',(64.3527939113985,12.08794524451,21.6575452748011));
#574=CARTESIAN_POINT('',(64.486002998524,12.0676867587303,21.7087703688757));
#575=CARTESIAN_POINT('',(64.7565531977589,12.0367390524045,21.8024885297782));
#576=CARTESIAN_POINT('',(64.8938943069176,12.026049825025,21.8449816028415));
#577=CARTESIAN_POINT('',(65.1714607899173,12.0145180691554,21.9206978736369));
#578=CARTESIAN_POINT('',(65.3116850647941,12.0136718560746,21.9539245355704));
#579=CARTESIAN_POINT('',(65.5937695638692,12.0218397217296,22.0108085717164));
#580=CARTESIAN_POINT('',(65.7356296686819,12.0308530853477,22.0344666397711));
#581=CARTESIAN_POINT('',(66.0037194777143,12.056948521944,22.0700102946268));
#582=CARTESIAN_POINT('',(66.1299158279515,12.0730110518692,22.0829194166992));
#583=CARTESIAN_POINT('',(66.3817598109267,12.1124121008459,22.1012162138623));
#584=CARTESIAN_POINT('',(66.5074072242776,12.1357532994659,22.106601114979));
#585=CARTESIAN_POINT('',(66.7573261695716,12.1892896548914,22.1100377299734));
#586=CARTESIAN_POINT('',(66.8815976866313,12.2194848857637,22.1080893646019));
#587=CARTESIAN_POINT('',(67.1281135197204,12.2862357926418,22.0971519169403));
#588=CARTESIAN_POINT('',(67.2503574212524,12.322792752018,22.0881614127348));
#589=CARTESIAN_POINT('',(67.5295561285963,12.4139070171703,22.059682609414));
#590=CARTESIAN_POINT('',(67.6855971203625,12.4705395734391,22.037812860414));
#591=CARTESIAN_POINT('',(67.9923006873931,12.5925512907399,21.9835014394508));
#592=CARTESIAN_POINT('',(68.1429618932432,12.6579326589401,21.9510570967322));
#593=CARTESIAN_POINT('',(68.5862137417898,12.8655859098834,21.8391334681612));
#594=CARTESIAN_POINT('',(68.8698547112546,13.0192932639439,21.7450880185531));
#595=CARTESIAN_POINT('',(69.5068058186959,13.4076855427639,21.485653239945));
#596=CARTESIAN_POINT('',(69.8488635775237,13.6516951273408,21.3067809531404));
#597=CARTESIAN_POINT('',(70.3238547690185,14.0368728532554,21.004329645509));
#598=CARTESIAN_POINT('',(70.4760089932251,14.168643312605,20.8976609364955));
#599=CARTESIAN_POINT('',(70.7677570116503,14.4373693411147,20.6740596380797));
#600=CARTESIAN_POINT('',(70.9073509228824,14.5743248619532,20.5571271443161));
#601=CARTESIAN_POINT('',(71.2138558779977,14.893768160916,20.2777875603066));
#602=CARTESIAN_POINT('',(71.376464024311,15.0776320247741,20.112233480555));
#603=CARTESIAN_POINT('',(71.6806866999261,15.4501036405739,19.7676231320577));
#604=CARTESIAN_POINT('',(71.8222934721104,15.6387131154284,19.5885619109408));
#605=CARTESIAN_POINT('',(72.0843474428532,16.0188285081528,19.2187623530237));
#606=CARTESIAN_POINT('',(72.2048082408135,16.2103324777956,19.0280316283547));
#607=CARTESIAN_POINT('',(72.4244440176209,16.5948526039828,18.6363231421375));
#608=CARTESIAN_POINT('',(72.523628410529,16.787868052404,18.4353499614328));
#609=CARTESIAN_POINT('',(72.6877995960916,17.1466581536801,18.0537334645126));
#610=CARTESIAN_POINT('',(72.7556458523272,17.3123934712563,17.8742764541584));
#611=CARTESIAN_POINT('',(72.8749371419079,17.6428910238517,17.5100786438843));
#612=CARTESIAN_POINT('',(72.9264268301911,17.8076546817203,17.3253537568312));
#613=CARTESIAN_POINT('',(72.9696650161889,17.9717962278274,17.1381491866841));
#614=B_SPLINE_CURVE_WITH_KNOTS('',3,(#546,#547,#548,#549,#550,#551,#552,#553,#554,#555,#556,
#557,#558,#559,#560,#561,#562,#563,#564,#565,#566,#567,#568,#569,#570,#571,#572,#573,#574,#575,
#576,#577,#578,#579,#580,#581,#582,#583,#584,#585,#586,#587,#588,#589,#590,#591,#592,#593,#594,
#595,#596,#597,#598,#599,#600,#601,#602,#603,#604,#605,#606,#607,#608,#609,#610,#611,#612,#613),
.UNSPECIFIED.,.F.,.F.,(4,2,2,2,2,2,2,2,2,2,2,2,2,2,2,2,2,2,2,2,2,2,2,2,2,2,2,2,2,2,2,2,2,4),(0.,
0.808334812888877,1.61670464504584,2.43435576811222,3.25206688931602,4.1948456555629,
5.13794999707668,6.07688428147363,7.01497063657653,8.06459723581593,9.1126950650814,
9.97002406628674,10.3989066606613,10.8275970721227,11.2594244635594,11.6912515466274,
12.1229169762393,12.554551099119,12.9377231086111,13.3210363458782,13.7043537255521,
14.0877485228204,14.5893065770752,15.0909914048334,16.0950460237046,17.4573554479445,
18.1402897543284,18.8232176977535,19.7102302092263,20.5975695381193,21.4843360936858,
22.3707094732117,23.1307194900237,23.888636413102),.UNSPECIFIED.);
#615=CARTESIAN_POINT('',(60.4714197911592,17.9717946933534,14.2527037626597));
#616=VERTEX_POINT('',#615);
#617=EDGE_CURVE('E313',#616,#541,#614,.T.);
#618=ORIENTED_EDGE('',*,*,#617,.F.);
#619=CARTESIAN_POINT('',(61.5165836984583,21.9456,9.72560151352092));
#620=CARTESIAN_POINT('',(61.342466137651,21.2829012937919,10.4797875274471));
#621=CARTESIAN_POINT('',(61.1683103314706,20.6204013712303,11.2341392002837));
#622=CARTESIAN_POINT('',(60.8199222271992,19.2957990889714,12.743173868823));
#623=CARTESIAN_POINT('',(60.6456899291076,18.6336967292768,13.497856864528));
#624=CARTESIAN_POINT('',(60.4714193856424,17.9717931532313,14.2527055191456));
#625=B_SPLINE_CURVE_WITH_KNOTS('',3,(#619,#620,#621,#622,#623,#624),.UNSPECIFIED.,.F.,.F.,(4,2,
4),(0.,3.05688494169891,6.11376990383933),.UNSPECIFIED.);
#626=EDGE_CURVE('E294',#186,#616,#625,.T.);
#627=ORIENTED_EDGE('',*,*,#626,.F.);
#628=ORIENTED_EDGE('',*,*,#187,.T.);
#629=CARTESIAN_POINT('',(57.1499999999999,21.15185,10.4436921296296));
#630=CARTESIAN_POINT('',(57.1499847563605,21.1846926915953,10.4056803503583));
#631=CARTESIAN_POINT('',(57.1479605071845,21.2175412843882,10.3676605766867));
#632=CARTESIAN_POINT('',(57.1397777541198,21.2830868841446,10.2917983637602));
#633=CARTESIAN_POINT('',(57.1336105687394,21.3157834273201,10.2539564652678));
#634=CARTESIAN_POINT('',(57.1169275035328,21.381102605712,10.1783643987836));
#635=CARTESIAN_POINT('',(57.1063614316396,21.4137198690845,10.140620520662));
#636=CARTESIAN_POINT('',(57.0806583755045,21.478153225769,10.0660756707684));
#637=CARTESIAN_POINT('',(57.0655260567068,21.5099701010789,10.0292737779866));
#638=CARTESIAN_POINT('',(57.0272414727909,21.5779867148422,9.95063343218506));
#639=CARTESIAN_POINT('',(57.0031440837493,21.6139662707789,9.90905549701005));
#640=CARTESIAN_POINT('',(56.9474782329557,21.6833178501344,9.82899256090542));
#641=CARTESIAN_POINT('',(56.9159353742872,21.7166982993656,9.79049755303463));
#642=CARTESIAN_POINT('',(56.8537756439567,21.7713218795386,9.72762872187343));
#643=CARTESIAN_POINT('',(56.8250453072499,21.793465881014,9.70218374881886));
#644=CARTESIAN_POINT('',(56.7626976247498,21.8346608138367,9.65497086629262));
#645=CARTESIAN_POINT('',(56.7290860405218,21.8537153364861,9.63319868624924));
#646=CARTESIAN_POINT('',(56.665778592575,21.8833819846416,9.5994692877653));
#647=CARTESIAN_POINT('',(56.6371081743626,21.8949209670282,9.58641218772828));
#648=CARTESIAN_POINT('',(56.5773473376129,21.9148324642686,9.56404686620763));
#649=CARTESIAN_POINT('',(56.5462633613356,21.9232130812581,9.5547290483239));
#650=CARTESIAN_POINT('',(56.4887894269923,21.9348873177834,9.54198362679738));
#651=CARTESIAN_POINT('',(56.4627181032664,21.9388662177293,9.53774681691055));
#652=CARTESIAN_POINT('',(56.409854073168,21.9442429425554,9.53231503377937));
#653=CARTESIAN_POINT('',(56.3830581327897,21.9456261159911,9.53113731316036));
#654=CARTESIAN_POINT('',(56.3562499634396,21.9456,9.53161504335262));
#655=B_SPLINE_CURVE_WITH_KNOTS('',3,(#629,#630,#631,#632,#633,#634,#635,#636,#637,#638,#639,
#640,#641,#642,#643,#644,#645,#646,#647,#648,#649,#650,#651,#652,#653,#654),.UNSPECIFIED.,.F.,
.F.,(4,2,2,2,2,2,2,2,2,2,2,2,4),(0.,0.15067962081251,0.301675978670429,0.45444461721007,
0.607057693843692,0.786664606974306,0.965662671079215,1.09817917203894,1.23054051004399,
1.33082093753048,1.4308423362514,1.5106788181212,1.59096459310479),.UNSPECIFIED.);
#656=CARTESIAN_POINT('',(57.15,21.15185,10.4436921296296));
#657=VERTEX_POINT('',#656);
#658=EDGE_CURVE('E215',#657,#177,#655,.T.);
#659=ORIENTED_EDGE('',*,*,#658,.F.);
#660=DIRECTION('',(0.,0.653777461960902,-0.756686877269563));
#661=VECTOR('',#660,1.);
#662=CARTESIAN_POINT('',(57.15,15.510408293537,16.973138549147));
#663=LINE('',#662,#661);
#664=CARTESIAN_POINT('',(57.15,9.76659464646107,23.6210710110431));
#665=VERTEX_POINT('',#664);
#666=EDGE_CURVE('E211',#665,#657,#663,.T.);
#667=ORIENTED_EDGE('',*,*,#666,.F.);
#668=CARTESIAN_POINT('',(57.15,9.76659464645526,23.6210710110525));
#669=CARTESIAN_POINT('',(57.1499908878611,9.74108281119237,23.650599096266));
#670=CARTESIAN_POINT('',(57.1483516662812,9.71557207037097,23.6801249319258));
#671=CARTESIAN_POINT('',(57.1418377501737,9.66470875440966,23.7389952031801));
#672=CARTESIAN_POINT('',(57.1369605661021,9.63935631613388,23.7683394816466));
#673=CARTESIAN_POINT('',(57.12392442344,9.58872910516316,23.8269434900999));
#674=CARTESIAN_POINT('',(57.1157300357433,9.56345823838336,23.856198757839));
#675=CARTESIAN_POINT('',(57.0960453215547,9.51349088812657,23.9140575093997));
#676=CARTESIAN_POINT('',(57.084556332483,9.48879417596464,23.9426612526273));
#677=CARTESIAN_POINT('',(57.0519156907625,9.42860811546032,24.0123984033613));
#678=CARTESIAN_POINT('',(57.0287674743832,9.39357450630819,24.0530180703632));
#679=CARTESIAN_POINT('',(56.9744904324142,9.32640485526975,24.1310050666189));
#680=CARTESIAN_POINT('',(56.9433947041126,9.29425752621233,24.168385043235));
#681=CARTESIAN_POINT('',(56.8804859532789,9.24121262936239,24.2302438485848));
#682=CARTESIAN_POINT('',(56.8504262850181,9.21941523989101,24.2557283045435));
#683=CARTESIAN_POINT('',(56.7853319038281,9.17925595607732,24.3028689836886));
#684=CARTESIAN_POINT('',(56.7502976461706,9.16089374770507,24.3245255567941));
#685=CARTESIAN_POINT('',(56.6823837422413,9.13166361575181,24.3592645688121));
#686=CARTESIAN_POINT('',(56.6502607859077,9.12004087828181,24.373189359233));
#687=CARTESIAN_POINT('',(56.5835492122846,9.10042087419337,24.3969862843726));
#688=CARTESIAN_POINT('',(56.5489673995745,9.09241402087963,24.4068691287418));
#689=CARTESIAN_POINT('',(56.4909699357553,9.08286596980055,24.4190498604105));
#690=CARTESIAN_POINT('',(56.4680644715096,9.08003248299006,24.4227990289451));
#691=CARTESIAN_POINT('',(56.4218024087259,9.07621046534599,24.4282201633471));
#692=CARTESIAN_POINT('',(56.3984448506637,9.07522642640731,24.4298870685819));
#693=CARTESIAN_POINT('',(56.3750398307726,9.07521658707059,24.4304532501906));
#694=B_SPLINE_CURVE_WITH_KNOTS('',3,(#668,#669,#670,#671,#672,#673,#674,#675,#676,#677,#678,
#679,#680,#681,#682,#683,#684,#685,#686,#687,#688,#689,#690,#691,#692,#693),.UNSPECIFIED.,.F.,
.F.,(4,2,2,2,2,2,2,2,2,2,2,2,4),(0.,0.11703039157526,0.234150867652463,0.352556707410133,
0.470914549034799,0.645586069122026,0.819541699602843,0.954148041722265,1.08874207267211,
1.19898843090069,1.30894075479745,1.37892766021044,1.44908432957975),.UNSPECIFIED.);
#695=CARTESIAN_POINT('',(56.3750398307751,9.07521658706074,24.430453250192));
#696=VERTEX_POINT('',#695);
#697=EDGE_CURVE('E214',#665,#696,#694,.T.);
#698=ORIENTED_EDGE('',*,*,#697,.T.);
#699=CARTESIAN_POINT('',(57.15,9.07521658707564,57.1499999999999));
#700=DIRECTION('',(0.,1.,0.));
#701=DIRECTION('',(0.224951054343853,0.,-0.974370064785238));
#702=AXIS2_PLACEMENT_3D('',#699,#700,#701);
#703=CIRCLE('',#702,32.7287229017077);
#704=EDGE_CURVE('E268',#543,#696,#703,.T.);
#705=ORIENTED_EDGE('',*,*,#704,.F.);
#706=EDGE_LOOP('',(#545,#618,#627,#628,#659,#667,#698,#705));
#707=FACE_BOUND('',#706,.T.);
#708=ADVANCED_FACE('F277',(#707),#535,.F.);
#709=CARTESIAN_POINT('',(66.7205426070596,21.9456,15.6954255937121));
#710=DIRECTION('',(0.,-1.,0.));
#711=DIRECTION('',(0.974370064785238,0.,0.224951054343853));
#712=AXIS2_PLACEMENT_3D('',#709,#710,#711);
#713=CYLINDRICAL_SURFACE('',#712,6.4135);
#714=ORIENTED_EDGE('',*,*,#617,.T.);
#715=DIRECTION('',(0.,-1.,0.));
#716=VECTOR('',#715,1.);
#717=CARTESIAN_POINT('',(65.2778190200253,21.9456,21.9445480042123));
#718=LINE('',#717,#716);
#719=EDGE_CURVE('E842',#541,#203,#718,.F.);
#720=ORIENTED_EDGE('',*,*,#719,.T.);
#721=ORIENTED_EDGE('',*,*,#204,.T.);
#722=DIRECTION('',(0.,-1.,0.));
#723=VECTOR('',#722,1.);
#724=CARTESIAN_POINT('',(60.4714201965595,17.9717910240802,14.2527020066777));
#725=LINE('',#724,#723);
#726=EDGE_CURVE('E314',#194,#616,#725,.T.);
#727=ORIENTED_EDGE('',*,*,#726,.T.);
#728=EDGE_LOOP('',(#714,#720,#721,#727));
#729=FACE_BOUND('',#728,.T.);
#730=ADVANCED_FACE('F282',(#729),#713,.T.);
#731=CARTESIAN_POINT('',(37.4879494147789,9.07521658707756,-3.17694284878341));
#732=DIRECTION('',(0.,1.,0.));
#733=DIRECTION('',(0.224951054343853,0.,-0.974370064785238));
#734=AXIS2_PLACEMENT_3D('',#731,#732,#733);
#735=PLANE('',#734);
#736=DIRECTION('',(0.974370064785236,0.,0.224951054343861));
#737=VECTOR('',#736,1.);
#738=CARTESIAN_POINT('',(25.2601121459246,9.07521658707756,49.7876392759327));
#739=LINE('',#738,#737);
#740=CARTESIAN_POINT('',(57.15,9.07521658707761,57.15));
#741=VERTEX_POINT('',#740);
#742=EDGE_CURVE('E813',#324,#741,#739,.T.);
#743=ORIENTED_EDGE('',*,*,#742,.T.);
#744=DIRECTION('',(0.224951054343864,0.,-0.974370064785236));
#745=VECTOR('',#744,1.);
#746=CARTESIAN_POINT('',(69.3778372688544,9.07521658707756,4.18541787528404));
#747=LINE('',#746,#745);
#748=EDGE_CURVE('E605',#741,#543,#747,.T.);
#749=ORIENTED_EDGE('',*,*,#748,.T.);
#750=ORIENTED_EDGE('',*,*,#704,.T.);
#751=CARTESIAN_POINT('',(57.1499999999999,9.07521658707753,57.1500000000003));
#752=DIRECTION('',(0.,1.,0.));
#753=DIRECTION('',(0.224951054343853,0.,-0.974370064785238));
#754=AXIS2_PLACEMENT_3D('',#751,#752,#753);
#755=CIRCLE('',#754,32.728722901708);
#756=EDGE_CURVE('E178',#696,#335,#755,.T.);
#757=ORIENTED_EDGE('',*,*,#756,.T.);
#758=ORIENTED_EDGE('',*,*,#336,.T.);
#759=EDGE_LOOP('',(#743,#749,#750,#757,#758));
#760=FACE_BOUND('',#759,.T.);
#761=ADVANCED_FACE('F318',(#760),#735,.T.);
#762=CARTESIAN_POINT('',(57.15,22.73935,57.15));
#763=DIRECTION('',(0.,1.,0.));
#764=DIRECTION('',(0.224951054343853,0.,-0.974370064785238));
#765=AXIS2_PLACEMENT_3D('',#762,#763,#764);
#766=TOROIDAL_SURFACE('',#765,53.56225,0.793749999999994);
#767=CARTESIAN_POINT('',(69.1988846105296,22.73935,4.960546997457));
#768=DIRECTION('',(0.974370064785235,0.,0.224951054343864));
#769=DIRECTION('',(0.224951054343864,0.,-0.974370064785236));
#770=AXIS2_PLACEMENT_3D('',#767,#768,#769);
#771=CIRCLE('',#770,0.793749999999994);
#772=CARTESIAN_POINT('',(69.3774395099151,22.7393499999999,4.18714075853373));
#773=VERTEX_POINT('',#772);
#774=EDGE_CURVE('E829',#773,#67,#771,.F.);
#775=ORIENTED_EDGE('',*,*,#774,.F.);
#776=CARTESIAN_POINT('',(57.15,22.73935,57.15));
#777=DIRECTION('',(0.,-1.,0.));
#778=DIRECTION('',(-0.224951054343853,0.,0.974370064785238));
#779=AXIS2_PLACEMENT_3D('',#776,#777,#778);
#780=CIRCLE('',#779,54.356);
#781=CARTESIAN_POINT('',(4.18714075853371,22.7393499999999,44.9225604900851));
#782=VERTEX_POINT('',#781);
#783=EDGE_CURVE('E197',#773,#782,#780,.F.);
#784=ORIENTED_EDGE('',*,*,#783,.T.);
#785=CARTESIAN_POINT('',(4.960546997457,22.73935,45.1011153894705));
#786=DIRECTION('',(-0.224951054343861,0.,0.974370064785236));
#787=DIRECTION('',(0.974370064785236,0.,0.224951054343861));
#788=AXIS2_PLACEMENT_3D('',#785,#786,#787);
#789=CIRCLE('',#788,0.793749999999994);
#790=EDGE_CURVE('E856',#78,#782,#789,.F.);
#791=ORIENTED_EDGE('',*,*,#790,.F.);
#792=ORIENTED_EDGE('',*,*,#79,.F.);
#793=EDGE_LOOP('',(#775,#784,#791,#792));
#794=FACE_BOUND('',#793,.T.);
#795=ADVANCED_FACE('F625',(#794),#766,.F.);
#796=CARTESIAN_POINT('',(57.15,32.0421,57.15));
#797=DIRECTION('',(0.,-1.,0.));
#798=DIRECTION('',(-0.224951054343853,0.,0.974370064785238));
#799=AXIS2_PLACEMENT_3D('',#796,#797,#798);
#800=CYLINDRICAL_SURFACE('',#799,54.356);
#801=DIRECTION('',(0.,-1.,0.));
#802=VECTOR('',#801,1.);
#803=CARTESIAN_POINT('',(69.3774395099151,32.0421000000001,4.18714075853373));
#804=LINE('',#803,#802);
#805=CARTESIAN_POINT('',(69.3774395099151,25.4,4.18714075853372));
#806=VERTEX_POINT('',#805);
#807=EDGE_CURVE('E827',#806,#773,#804,.T.);
#808=ORIENTED_EDGE('',*,*,#807,.F.);
#809=CARTESIAN_POINT('',(57.15,25.4,57.15));
#810=DIRECTION('',(0.,-1.,0.));
#811=DIRECTION('',(-0.224951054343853,0.,0.974370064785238));
#812=AXIS2_PLACEMENT_3D('',#809,#810,#811);
#813=CIRCLE('',#812,54.356);
#814=CARTESIAN_POINT('',(4.1871407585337,25.4,44.9225604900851));
#815=VERTEX_POINT('',#814);
#816=EDGE_CURVE('E202',#806,#815,#813,.F.);
#817=ORIENTED_EDGE('',*,*,#816,.T.);
#818=DIRECTION('',(0.,-1.,0.));
#819=VECTOR('',#818,1.);
#820=CARTESIAN_POINT('',(4.1871407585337,32.0421,44.9225604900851));
#821=LINE('',#820,#819);
#822=EDGE_CURVE('E859',#782,#815,#821,.F.);
#823=ORIENTED_EDGE('',*,*,#822,.F.);
#824=ORIENTED_EDGE('',*,*,#783,.F.);
#825=EDGE_LOOP('',(#808,#817,#823,#824));
#826=FACE_BOUND('',#825,.T.);
#827=ADVANCED_FACE('F628',(#826),#800,.F.);
#828=CARTESIAN_POINT('',(57.15,25.4,57.15));
#829=DIRECTION('',(0.,-1.,0.));
#830=DIRECTION('',(-0.224951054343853,0.,0.974370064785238));
#831=AXIS2_PLACEMENT_3D('',#828,#829,#830);
#832=PLANE('',#831);
#833=DIRECTION('',(-0.224951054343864,0.,0.974370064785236));
#834=VECTOR('',#833,1.);
#835=CARTESIAN_POINT('',(57.15,25.4,57.15));
#836=LINE('',#835,#834);
#837=CARTESIAN_POINT('',(70.0059527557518,25.4,1.46475079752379));
#838=VERTEX_POINT('',#837);
#839=EDGE_CURVE('E820',#838,#806,#836,.T.);
#840=ORIENTED_EDGE('',*,*,#839,.F.);
#841=CARTESIAN_POINT('',(57.15,25.4,57.15));
#842=DIRECTION('',(0.,1.,0.));
#843=DIRECTION('',(0.224951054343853,0.,-0.974370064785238));
#844=AXIS2_PLACEMENT_3D('',#841,#842,#843);
#845=CIRCLE('',#844,57.15);
#846=CARTESIAN_POINT('',(1.46475079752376,25.4,44.2940472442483));
#847=VERTEX_POINT('',#846);
#848=EDGE_CURVE('E205',#847,#838,#845,.F.);
#849=ORIENTED_EDGE('',*,*,#848,.F.);
#850=DIRECTION('',(-0.974370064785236,0.,-0.224951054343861));
#851=VECTOR('',#850,1.);
#852=CARTESIAN_POINT('',(57.15,25.4,57.15));
#853=LINE('',#852,#851);
#854=EDGE_CURVE('E864',#815,#847,#853,.T.);
#855=ORIENTED_EDGE('',*,*,#854,.F.);
#856=ORIENTED_EDGE('',*,*,#816,.F.);
#857=EDGE_LOOP('',(#840,#849,#855,#856));
#858=FACE_BOUND('',#857,.T.);
#859=ADVANCED_FACE('F632',(#858),#832,.F.);
#860=CARTESIAN_POINT('',(57.15,0.,57.15));
#861=DIRECTION('',(0.,1.,0.));
#862=DIRECTION('',(0.224951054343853,0.,-0.974370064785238));
#863=AXIS2_PLACEMENT_3D('',#860,#861,#862);
#864=CYLINDRICAL_SURFACE('',#863,57.15);
#865=ORIENTED_EDGE('',*,*,#848,.T.);
#866=DIRECTION('',(0.,1.,0.));
#867=VECTOR('',#866,1.);
#868=CARTESIAN_POINT('',(70.0059527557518,0.,1.46475079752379));
#869=LINE('',#868,#867);
#870=CARTESIAN_POINT('',(70.0059527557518,0.,1.46475079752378));
#871=VERTEX_POINT('',#870);
#872=EDGE_CURVE('E816',#838,#871,#869,.F.);
#873=ORIENTED_EDGE('',*,*,#872,.T.);
#874=CARTESIAN_POINT('',(57.15,0.,57.15));
#875=DIRECTION('',(0.,1.,0.));
#876=DIRECTION('',(0.224951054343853,0.,-0.974370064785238));
#877=AXIS2_PLACEMENT_3D('',#874,#875,#876);
#878=CIRCLE('',#877,57.15);
#879=CARTESIAN_POINT('',(1.46475079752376,0.,44.2940472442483));
#880=VERTEX_POINT('',#879);
#881=EDGE_CURVE('E208',#880,#871,#878,.F.);
#882=ORIENTED_EDGE('',*,*,#881,.F.);
#883=DIRECTION('',(0.,1.,0.));
#884=VECTOR('',#883,1.);
#885=CARTESIAN_POINT('',(1.46475079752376,0.,44.2940472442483));
#886=LINE('',#885,#884);
#887=EDGE_CURVE('E61',#880,#847,#886,.T.);
#888=ORIENTED_EDGE('',*,*,#887,.T.);
#889=EDGE_LOOP('',(#865,#873,#882,#888));
#890=FACE_BOUND('',#889,.T.);
#891=ADVANCED_FACE('F636',(#890),#864,.T.);
#892=CARTESIAN_POINT('',(57.15,0.,57.15));
#893=DIRECTION('',(0.,-1.,0.));
#894=DIRECTION('',(-0.224951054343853,0.,0.974370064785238));
#895=AXIS2_PLACEMENT_3D('',#892,#893,#894);
#896=PLANE('',#895);
#897=ORIENTED_EDGE('',*,*,#881,.T.);
#898=DIRECTION('',(-0.224951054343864,0.,0.974370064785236));
#899=VECTOR('',#898,1.);
#900=CARTESIAN_POINT('',(57.15,0.,57.15));
#901=LINE('',#900,#899);
#902=CARTESIAN_POINT('',(57.15,0.,57.15));
#903=VERTEX_POINT('',#902);
#904=EDGE_CURVE('E11',#871,#903,#901,.T.);
#905=ORIENTED_EDGE('',*,*,#904,.T.);
#906=DIRECTION('',(-0.974370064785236,0.,-0.224951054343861));
#907=VECTOR('',#906,1.);
#908=CARTESIAN_POINT('',(57.15,0.,57.15));
#909=LINE('',#908,#907);
#910=EDGE_CURVE('E53',#903,#880,#909,.T.);
#911=ORIENTED_EDGE('',*,*,#910,.T.);
#912=EDGE_LOOP('',(#897,#905,#911));
#913=FACE_BOUND('',#912,.T.);
#914=ADVANCED_FACE('F624',(#913),#896,.T.);
#915=CARTESIAN_POINT('',(28.0832573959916,8.99306019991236,42.1109816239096));
#916=CARTESIAN_POINT('',(28.0501987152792,8.9930605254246,42.1748759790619));
#917=CARTESIAN_POINT('',(28.0070511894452,9.00272582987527,42.2346430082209));
#918=CARTESIAN_POINT('',(27.9114071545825,9.03685550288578,42.3360695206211));
#919=CARTESIAN_POINT('',(27.8578008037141,9.06150338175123,42.3794125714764));
#920=CARTESIAN_POINT('',(27.7272068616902,9.13105548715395,42.4615842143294));
#921=CARTESIAN_POINT('',(27.6466877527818,9.18117167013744,42.4943859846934));
#922=CARTESIAN_POINT('',(27.5676994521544,9.23561469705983,42.5133028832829));
#923=CARTESIAN_POINT('',(27.5675441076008,9.23572178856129,42.5133400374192));
#924=CARTESIAN_POINT('',(27.4602817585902,9.30967988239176,42.5389602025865));
#925=CARTESIAN_POINT('',(27.3528142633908,9.39308638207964,42.5411992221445));
#926=CARTESIAN_POINT('',(27.1694509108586,9.54768615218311,42.5133238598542));
#927=CARTESIAN_POINT('',(27.0896463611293,9.61984861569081,42.4885859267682));
#928=CARTESIAN_POINT('',(27.0159255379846,9.69153163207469,42.4526298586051));
#929=CARTESIAN_POINT('',(28.0827003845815,9.02044566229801,42.1107094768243));
#930=CARTESIAN_POINT('',(28.0496581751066,9.02044587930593,42.1745720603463));
#931=CARTESIAN_POINT('',(28.0065389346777,9.03007862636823,42.2343094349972));
#932=CARTESIAN_POINT('',(27.9109486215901,9.06409334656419,42.3357051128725));
#933=CARTESIAN_POINT('',(27.8573716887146,9.08865823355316,42.3790417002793));
#934=CARTESIAN_POINT('',(27.7268279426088,9.15797583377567,42.461223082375));
#935=CARTESIAN_POINT('',(27.6463296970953,9.2079229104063,42.4940451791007));
#936=CARTESIAN_POINT('',(27.5673419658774,9.2621818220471,42.5129860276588));
#937=CARTESIAN_POINT('',(27.5671866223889,9.26228855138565,42.5130232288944));
#938=CARTESIAN_POINT('',(27.4599249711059,9.33599653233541,42.53867591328));
#939=CARTESIAN_POINT('',(27.352434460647,9.41912045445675,42.540945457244));
#940=CARTESIAN_POINT('',(27.1690047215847,9.57319562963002,42.5130914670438));
#941=CARTESIAN_POINT('',(27.0891669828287,9.64511307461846,42.4883521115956));
#942=CARTESIAN_POINT('',(27.0154164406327,9.71655263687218,42.4523815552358));
#943=CARTESIAN_POINT('',(28.0821433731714,9.04783112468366,42.110437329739));
#944=CARTESIAN_POINT('',(28.049117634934,9.04783123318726,42.1742681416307));
#945=CARTESIAN_POINT('',(28.0060266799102,9.0574314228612,42.2339758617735));
#946=CARTESIAN_POINT('',(27.9104900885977,9.0913311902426,42.3353407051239));
#947=CARTESIAN_POINT('',(27.856942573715,9.1158130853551,42.3786708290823));
#948=CARTESIAN_POINT('',(27.7264490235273,9.18489618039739,42.4608619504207));
#949=CARTESIAN_POINT('',(27.6459716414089,9.23467415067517,42.4937043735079));
#950=CARTESIAN_POINT('',(27.5669844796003,9.28874894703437,42.5126691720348));
#951=CARTESIAN_POINT('',(27.566829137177,9.28885531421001,42.5127064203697));
#952=CARTESIAN_POINT('',(27.4595681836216,9.36231318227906,42.5383916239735));
#953=CARTESIAN_POINT('',(27.3520546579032,9.44515452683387,42.5406916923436));
#954=CARTESIAN_POINT('',(27.1685585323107,9.59870510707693,42.5128590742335));
#955=CARTESIAN_POINT('',(27.0886876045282,9.67037753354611,42.488118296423));
#956=CARTESIAN_POINT('',(27.0149073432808,9.74157364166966,42.4521332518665));
#957=CARTESIAN_POINT('',(28.0815863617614,9.07521658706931,42.1101651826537));
#958=CARTESIAN_POINT('',(28.0485770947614,9.07521658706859,42.1739642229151));
#959=CARTESIAN_POINT('',(28.0055144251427,9.08478421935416,42.2336422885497));
#960=CARTESIAN_POINT('',(27.9100315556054,9.11856903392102,42.3349762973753));
#961=CARTESIAN_POINT('',(27.8565134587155,9.14296793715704,42.3782999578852));
#962=CARTESIAN_POINT('',(27.7260701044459,9.21181652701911,42.4605008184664));
#963=CARTESIAN_POINT('',(27.6456135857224,9.26142539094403,42.4933635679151));
#964=CARTESIAN_POINT('',(27.5666269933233,9.31531607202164,42.5123523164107));
#965=CARTESIAN_POINT('',(27.5664716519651,9.31542207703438,42.5123896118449));
#966=CARTESIAN_POINT('',(27.4592113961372,9.38862983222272,42.538107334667));
#967=CARTESIAN_POINT('',(27.3516748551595,9.47118859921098,42.5404379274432));
#968=CARTESIAN_POINT('',(27.1681123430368,9.62421458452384,42.5126266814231));
#969=CARTESIAN_POINT('',(27.0882082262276,9.69564199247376,42.4878844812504));
#970=CARTESIAN_POINT('',(27.0143982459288,9.76659464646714,42.4518849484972));
#971=CARTESIAN_POINT('',(28.0258852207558,11.8137628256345,42.0829504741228));
#972=CARTESIAN_POINT('',(27.9945230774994,11.8137519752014,42.1435723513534));
#973=CARTESIAN_POINT('',(27.9542889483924,11.8200638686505,42.2002849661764));
#974=CARTESIAN_POINT('',(27.8641782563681,11.8423534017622,42.2985355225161));
#975=CARTESIAN_POINT('',(27.8136019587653,11.8584531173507,42.3412128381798));
#976=CARTESIAN_POINT('',(27.6881781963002,11.9038511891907,42.4243876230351));
#977=CARTESIAN_POINT('',(27.6098080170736,11.9365494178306,42.4592830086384));
#978=CARTESIAN_POINT('',(27.5308783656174,11.9720285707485,42.480666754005));
#979=CARTESIAN_POINT('',(27.530723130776,11.9720983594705,42.4807087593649));
#980=CARTESIAN_POINT('',(27.4235326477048,12.020294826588,42.5096784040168));
#981=CARTESIAN_POINT('',(27.3136945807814,12.0745958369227,42.5150614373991));
#982=CARTESIAN_POINT('',(27.1234934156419,12.175162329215,42.4893874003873));
#983=CARTESIAN_POINT('',(27.0402703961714,12.2220878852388,42.4645029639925));
#984=CARTESIAN_POINT('',(26.9634885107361,12.2686951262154,42.4270546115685));
#985=CARTESIAN_POINT('',(27.9701804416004,14.5523090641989,42.055742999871));
#986=CARTESIAN_POINT('',(27.9404656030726,14.5522873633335,42.1131873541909));
#987=CARTESIAN_POINT('',(27.9030601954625,14.5553435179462,42.1669341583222));
#988=CARTESIAN_POINT('',(27.8183220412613,14.5661377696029,42.2621005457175));
#989=CARTESIAN_POINT('',(27.7706877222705,14.5739382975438,42.3041311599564));
#990=CARTESIAN_POINT('',(27.6502839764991,14.5958858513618,42.3882790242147));
#991=CARTESIAN_POINT('',(27.5740003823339,14.6116734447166,42.4252065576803));
#992=CARTESIAN_POINT('',(27.4951279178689,14.6287410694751,42.4489848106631));
#993=CARTESIAN_POINT('',(27.4949727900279,14.6287746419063,42.4490315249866));
#994=CARTESIAN_POINT('',(27.3878524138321,14.651959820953,42.4812524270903));
#995=CARTESIAN_POINT('',(27.2757131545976,14.6780030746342,42.4896872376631));
#996=CARTESIAN_POINT('',(27.0788739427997,14.7261100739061,42.4661492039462));
#997=CARTESIAN_POINT('',(26.9923322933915,14.7485337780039,42.441121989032));
#998=CARTESIAN_POINT('',(26.9125787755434,14.7707956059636,42.4022242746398));
#999=CARTESIAN_POINT('',(27.9144720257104,17.2908553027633,42.0285427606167));
#1000=CARTESIAN_POINT('',(27.8864046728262,17.2908227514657,42.0828092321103));
#1001=CARTESIAN_POINT('',(27.8518281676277,17.2906231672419,42.1335898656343));
#1002=CARTESIAN_POINT('',(27.7724629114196,17.2899221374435,42.2256713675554));
#1003=CARTESIAN_POINT('',(27.7277707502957,17.2894234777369,42.2670549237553));
#1004=CARTESIAN_POINT('',(27.6123874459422,17.2879205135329,42.3521750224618));
#1005=CARTESIAN_POINT('',(27.538190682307,17.2867974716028,42.3911342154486));
#1006=CARTESIAN_POINT('',(27.4593756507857,17.2854535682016,42.4173064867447));
#1007=CARTESIAN_POINT('',(27.459220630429,17.285450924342,42.4173579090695));
#1008=CARTESIAN_POINT('',(27.352170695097,17.283624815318,42.4528294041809));
#1009=CARTESIAN_POINT('',(27.2377305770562,17.2814103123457,42.4643153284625));
#1010=CARTESIAN_POINT('',(27.0342539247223,17.2770578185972,42.4429120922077));
#1011=CARTESIAN_POINT('',(26.944393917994,17.2749796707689,42.4177415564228));
#1012=CARTESIAN_POINT('',(26.8616690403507,17.2728960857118,42.377393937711));
#1013=B_SPLINE_SURFACE_WITH_KNOTS('',3,3,((#915,#916,#917,#918,#919,#920,#921,#922,#923,#924,
#925,#926,#927,#928),(#929,#930,#931,#932,#933,#934,#935,#936,#937,#938,#939,#940,#941,#942),
(#943,#944,#945,#946,#947,#948,#949,#950,#951,#952,#953,#954,#955,#956),(#957,#958,#959,#960,
#961,#962,#963,#964,#965,#966,#967,#968,#969,#970),(#971,#972,#973,#974,#975,#976,#977,#978,
#979,#980,#981,#982,#983,#984),(#985,#986,#987,#988,#989,#990,#991,#992,#993,#994,#995,#996,
#997,#998),(#999,#1000,#1001,#1002,#1003,#1004,#1005,#1006,#1007,#1008,#1009,#1010,#1011,
#1012)),.UNSPECIFIED.,.F.,.F.,.F.,(4,3,4),(4,2,2,2,2,2,4),(-0.01,0.,1.),(0.,0.149239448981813,
0.29710987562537,0.499600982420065,0.5,0.775113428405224,1.),.UNSPECIFIED.);
#1014=CARTESIAN_POINT('',(28.0832573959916,8.99306019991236,42.1109816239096));
#1015=CARTESIAN_POINT('',(28.0827003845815,9.02044566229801,42.1107094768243));
#1016=CARTESIAN_POINT('',(28.0821433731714,9.04783112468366,42.110437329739));
#1017=CARTESIAN_POINT('',(28.0815863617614,9.07521658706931,42.1101651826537));
#1018=CARTESIAN_POINT('',(28.0258852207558,11.8137628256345,42.0829504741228));
#1019=CARTESIAN_POINT('',(27.9701804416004,14.5523090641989,42.055742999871));
#1020=CARTESIAN_POINT('',(27.9144720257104,17.2908553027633,42.0285427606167));
#1021=B_SPLINE_CURVE_WITH_KNOTS('',3,(#1014,#1015,#1016,#1017,#1018,#1019,#1020),.UNSPECIFIED.,
.F.,.F.,(4,3,4),(-0.01,0.,1.),.UNSPECIFIED.);
#1022=CARTESIAN_POINT('',(27.9144720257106,17.2908553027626,42.0285427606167));
#1023=VERTEX_POINT('',#1022);
#1024=EDGE_CURVE('E182',#335,#1023,#1021,.T.);
#1025=CARTESIAN_POINT('',(27.9144720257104,17.2908553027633,42.0285427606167));
#1026=CARTESIAN_POINT('',(27.8864046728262,17.2908227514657,42.0828092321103));
#1027=CARTESIAN_POINT('',(27.8518281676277,17.2906231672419,42.1335898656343));
#1028=CARTESIAN_POINT('',(27.7724629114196,17.2899221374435,42.2256713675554));
#1029=CARTESIAN_POINT('',(27.7277707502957,17.2894234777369,42.2670549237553));
#1030=CARTESIAN_POINT('',(27.6123874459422,17.2879205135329,42.3521750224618));
#1031=CARTESIAN_POINT('',(27.538190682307,17.2867974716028,42.3911342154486));
#1032=CARTESIAN_POINT('',(27.4593756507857,17.2854535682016,42.4173064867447));
#1033=CARTESIAN_POINT('',(27.459220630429,17.285450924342,42.4173579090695));
#1034=CARTESIAN_POINT('',(27.352170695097,17.283624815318,42.4528294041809));
#1035=CARTESIAN_POINT('',(27.2377305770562,17.2814103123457,42.4643153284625));
#1036=CARTESIAN_POINT('',(27.0342539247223,17.2770578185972,42.4429120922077));
#1037=CARTESIAN_POINT('',(26.944393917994,17.2749796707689,42.4177415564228));
#1038=CARTESIAN_POINT('',(26.8616690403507,17.2728960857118,42.377393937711));
#1039=B_SPLINE_CURVE_WITH_KNOTS('',3,(#1025,#1026,#1027,#1028,#1029,#1030,#1031,#1032,#1033,
#1034,#1035,#1036,#1037,#1038),.UNSPECIFIED.,.F.,.F.,(4,2,2,2,2,2,4),(0.,0.149239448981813,
0.29710987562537,0.499600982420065,0.5,0.775113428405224,1.),.UNSPECIFIED.);
#1040=CARTESIAN_POINT('',(26.8616690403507,17.2728960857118,42.377393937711));
#1041=VERTEX_POINT('',#1040);
#1042=EDGE_CURVE('E143',#1023,#1041,#1039,.T.);
#1043=DIRECTION('',(0.0203415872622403,-0.999743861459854,0.0099212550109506));
#1044=VECTOR('',#1043,1.);
#1045=CARTESIAN_POINT('',(26.8616690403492,17.2728960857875,42.3773939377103));
#1046=LINE('',#1045,#1044);
#1047=EDGE_CURVE('E107',#1041,#368,#1046,.T.);
#1048=ORIENTED_EDGE('',*,*,#1024,.T.);
#1049=ORIENTED_EDGE('',*,*,#1042,.T.);
#1050=ORIENTED_EDGE('',*,*,#1047,.T.);
#1051=ORIENTED_EDGE('',*,*,#369,.F.);
#1052=EDGE_LOOP('',(#1048,#1049,#1050,#1051));
#1053=FACE_BOUND('',#1052,.T.);
#1054=ADVANCED_FACE('F42',(#1053),#1013,.T.);
#1055=CARTESIAN_POINT('',(57.15,9.69153163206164,23.6227702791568));
#1056=CARTESIAN_POINT('',(57.1500000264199,9.58822873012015,23.740963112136));
#1057=CARTESIAN_POINT('',(57.1236178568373,9.48336393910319,23.8609376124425));
#1058=CARTESIAN_POINT('',(57.0435662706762,9.33406811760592,24.0320867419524));
#1059=CARTESIAN_POINT('',(57.0077854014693,9.28332950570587,24.0903342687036));
#1060=CARTESIAN_POINT('',(56.9462473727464,9.21825155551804,24.1652882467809));
#1061=CARTESIAN_POINT('',(56.9277632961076,9.20064457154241,24.1855962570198));
#1062=CARTESIAN_POINT('',(56.8533153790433,9.13723870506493,24.2588623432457));
#1063=CARTESIAN_POINT('',(56.7872169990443,9.09539232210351,24.3075206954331));
#1064=CARTESIAN_POINT('',(56.6517955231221,9.03666611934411,24.3767616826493));
#1065=CARTESIAN_POINT('',(56.5837124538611,9.01607616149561,24.40150813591));
#1066=CARTESIAN_POINT('',(56.4680351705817,8.99700231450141,24.4256800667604));
#1067=CARTESIAN_POINT('',(56.421438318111,8.99306040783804,24.4312140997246));
#1068=CARTESIAN_POINT('',(56.375041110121,8.99306019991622,24.4323130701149));
#1069=CARTESIAN_POINT('',(57.15,9.71655263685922,23.6222038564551));
#1070=CARTESIAN_POINT('',(57.1500000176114,9.61360064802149,23.7404474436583));
#1071=CARTESIAN_POINT('',(57.1235883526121,9.5090918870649,23.8604651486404));
#1072=CARTESIAN_POINT('',(57.0434758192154,9.3603021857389,24.0316411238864));
#1073=CARTESIAN_POINT('',(57.0076730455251,9.30973534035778,24.0898869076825));
#1074=CARTESIAN_POINT('',(56.9461106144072,9.24487744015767,24.1648263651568));
#1075=CARTESIAN_POINT('',(56.9276204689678,9.22732995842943,24.1851289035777));
#1076=CARTESIAN_POINT('',(56.8531546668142,9.16413827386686,24.2583705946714));
#1077=CARTESIAN_POINT('',(56.7870577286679,9.12243297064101,24.3069996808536));
#1078=CARTESIAN_POINT('',(56.6516644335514,9.06390465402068,24.3761919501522));
#1079=CARTESIAN_POINT('',(56.5836086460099,9.04338399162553,24.4009160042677));
#1080=CARTESIAN_POINT('',(56.4679848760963,9.0243744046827,24.4250660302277));
#1081=CARTESIAN_POINT('',(56.4214134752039,9.02044580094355,24.4305947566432));
#1082=CARTESIAN_POINT('',(56.3750406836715,9.02044566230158,24.4316931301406));
#1083=CARTESIAN_POINT('',(57.15,9.7415736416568,23.6216374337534));
#1084=CARTESIAN_POINT('',(57.1500000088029,9.63897256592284,23.7399317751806));
#1085=CARTESIAN_POINT('',(57.1235588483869,9.53481983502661,23.8599926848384));
#1086=CARTESIAN_POINT('',(57.0433853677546,9.38653625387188,24.0311955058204));
#1087=CARTESIAN_POINT('',(57.007560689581,9.3361411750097,24.0894395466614));
#1088=CARTESIAN_POINT('',(56.9459738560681,9.27150332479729,24.1643644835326));
#1089=CARTESIAN_POINT('',(56.9274776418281,9.25401534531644,24.1846615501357));
#1090=CARTESIAN_POINT('',(56.8529939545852,9.19103784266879,24.2578788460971));
#1091=CARTESIAN_POINT('',(56.7868984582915,9.1494736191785,24.3064786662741));
#1092=CARTESIAN_POINT('',(56.6515333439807,9.09114318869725,24.375622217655));
#1093=CARTESIAN_POINT('',(56.5835048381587,9.07069182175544,24.4003238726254));
#1094=CARTESIAN_POINT('',(56.467934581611,9.051746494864,24.4244519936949));
#1095=CARTESIAN_POINT('',(56.4213886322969,9.04783119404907,24.4299754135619));
#1096=CARTESIAN_POINT('',(56.3750402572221,9.04783112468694,24.4310731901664));
#1097=CARTESIAN_POINT('',(57.15,9.76659464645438,23.6210710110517));
#1098=CARTESIAN_POINT('',(57.1499999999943,9.66434448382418,23.7394161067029));
#1099=CARTESIAN_POINT('',(57.1235293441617,9.56054778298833,23.8595202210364));
#1100=CARTESIAN_POINT('',(57.0432949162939,9.41277032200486,24.0307498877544));
#1101=CARTESIAN_POINT('',(57.0074483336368,9.36254700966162,24.0889921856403));
#1102=CARTESIAN_POINT('',(56.9458370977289,9.29812920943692,24.1639026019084));
#1103=CARTESIAN_POINT('',(56.9273348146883,9.28070073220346,24.1841941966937));
#1104=CARTESIAN_POINT('',(56.8528332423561,9.21793741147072,24.2573870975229));
#1105=CARTESIAN_POINT('',(56.7867391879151,9.176514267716,24.3059576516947));
#1106=CARTESIAN_POINT('',(56.65140225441,9.11838172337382,24.3750524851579));
#1107=CARTESIAN_POINT('',(56.5834010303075,9.09799965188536,24.3997317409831));
#1108=CARTESIAN_POINT('',(56.4678842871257,9.07911858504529,24.4238379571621));
#1109=CARTESIAN_POINT('',(56.4213637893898,9.07521658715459,24.4293560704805));
#1110=CARTESIAN_POINT('',(56.3750398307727,9.0752165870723,24.4304532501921));
#1111=CARTESIAN_POINT('',(57.15,12.2686951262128,23.5644287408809));
#1112=CARTESIAN_POINT('',(57.1499991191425,12.2015362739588,23.6878492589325));
#1113=CARTESIAN_POINT('',(57.1205789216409,12.1333425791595,23.8122738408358));
#1114=CARTESIAN_POINT('',(57.0342497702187,12.0361771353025,23.9861880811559));
#1115=CARTESIAN_POINT('',(56.9962127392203,12.0031304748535,24.0442560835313));
#1116=CARTESIAN_POINT('',(56.932161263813,11.9607176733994,24.1177144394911));
#1117=CARTESIAN_POINT('',(56.9130521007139,11.9492394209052,24.137458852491));
#1118=CARTESIAN_POINT('',(56.8367620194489,11.9078942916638,24.2082122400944));
#1119=CARTESIAN_POINT('',(56.7708121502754,11.880579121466,24.2538561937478));
#1120=CARTESIAN_POINT('',(56.638293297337,11.8422351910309,24.3180792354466));
#1121=CARTESIAN_POINT('',(56.5730202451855,11.8287826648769,24.3405185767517));
#1122=CARTESIAN_POINT('',(56.4628548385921,11.8163276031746,24.3624343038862));
#1123=CARTESIAN_POINT('',(56.4188794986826,11.8137558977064,24.3674217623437));
#1124=CARTESIAN_POINT('',(56.3749971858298,11.8137628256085,24.3684592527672));
#1125=CARTESIAN_POINT('',(57.15,14.7707956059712,23.50778647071));
#1126=CARTESIAN_POINT('',(57.1499991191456,14.7387280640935,23.636282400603));
#1127=CARTESIAN_POINT('',(57.1176302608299,14.7061373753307,23.765027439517));
#1128=CARTESIAN_POINT('',(57.0252077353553,14.6595839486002,23.9416262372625));
#1129=CARTESIAN_POINT('',(56.9849807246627,14.6437139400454,23.9995199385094));
#1130=CARTESIAN_POINT('',(56.9184896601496,14.6233061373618,24.0715262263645));
#1131=CARTESIAN_POINT('',(56.8987737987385,14.6177781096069,24.0907234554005));
#1132=CARTESIAN_POINT('',(56.8206958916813,14.597851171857,24.1590373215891));
#1133=CARTESIAN_POINT('',(56.7548907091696,14.584643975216,24.2017546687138));
#1134=CARTESIAN_POINT('',(56.6251908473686,14.566088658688,24.2611059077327));
#1135=CARTESIAN_POINT('',(56.5626463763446,14.5595656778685,24.2813053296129));
#1136=CARTESIAN_POINT('',(56.4578329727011,14.5535366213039,24.301030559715));
#1137=CARTESIAN_POINT('',(56.4164030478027,14.5522952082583,24.3054873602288));
#1138=CARTESIAN_POINT('',(56.3749626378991,14.5523090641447,24.306465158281));
#1139=CARTESIAN_POINT('',(57.15,17.2728960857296,23.4511442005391));
#1140=CARTESIAN_POINT('',(57.15,17.2759198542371,23.5847155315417));
#1141=CARTESIAN_POINT('',(57.1146833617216,17.2789321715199,23.7177810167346));
#1142=CARTESIAN_POINT('',(57.0161688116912,17.2829907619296,23.8970643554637));
#1143=CARTESIAN_POINT('',(56.9737522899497,17.2842974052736,23.9547837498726));
#1144=CARTESIAN_POINT('',(56.9048222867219,17.2858946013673,24.0253379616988));
#1145=CARTESIAN_POINT('',(56.8844999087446,17.2863167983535,24.0439880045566));
#1146=CARTESIAN_POINT('',(56.8046348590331,17.2878080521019,24.1098623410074));
#1147=CARTESIAN_POINT('',(56.738974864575,17.2887088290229,24.1496530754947));
#1148=CARTESIAN_POINT('',(56.6120949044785,17.2899421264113,24.2041325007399));
#1149=CARTESIAN_POINT('',(56.5522794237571,17.2903486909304,24.22209199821));
#1150=CARTESIAN_POINT('',(56.4528186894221,17.2907456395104,24.2396267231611));
#1151=CARTESIAN_POINT('',(56.4139344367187,17.2908345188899,24.2435528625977));
#1152=CARTESIAN_POINT('',(56.3749361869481,17.2908553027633,24.2444709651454));
#1153=B_SPLINE_SURFACE_WITH_KNOTS('',3,3,((#1055,#1056,#1057,#1058,#1059,#1060,#1061,#1062,
#1063,#1064,#1065,#1066,#1067,#1068),(#1069,#1070,#1071,#1072,#1073,#1074,#1075,#1076,#1077,
#1078,#1079,#1080,#1081,#1082),(#1083,#1084,#1085,#1086,#1087,#1088,#1089,#1090,#1091,#1092,
#1093,#1094,#1095,#1096),(#1097,#1098,#1099,#1100,#1101,#1102,#1103,#1104,#1105,#1106,#1107,
#1108,#1109,#1110),(#1111,#1112,#1113,#1114,#1115,#1116,#1117,#1118,#1119,#1120,#1121,#1122,
#1123,#1124),(#1125,#1126,#1127,#1128,#1129,#1130,#1131,#1132,#1133,#1134,#1135,#1136,#1137,
#1138),(#1139,#1140,#1141,#1142,#1143,#1144,#1145,#1146,#1147,#1148,#1149,#1150,#1151,#1152)),
.UNSPECIFIED.,.F.,.F.,.F.,(4,3,4),(4,2,2,2,2,2,4),(-0.01,0.,1.),(0.,0.32636293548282,0.5,
0.567338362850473,0.75310840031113,0.904711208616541,1.),.UNSPECIFIED.);
#1154=DIRECTION('',(0.,0.999743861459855,-0.0226320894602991));
#1155=VECTOR('',#1154,1.);
#1156=CARTESIAN_POINT('',(57.15,9.76659464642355,23.6210710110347));
#1157=LINE('',#1156,#1155);
#1158=CARTESIAN_POINT('',(57.15,17.2728960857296,23.4511442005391));
#1159=VERTEX_POINT('',#1158);
#1160=EDGE_CURVE('E195',#665,#1159,#1157,.T.);
#1161=CARTESIAN_POINT('',(57.15,17.2728960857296,23.4511442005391));
#1162=CARTESIAN_POINT('',(57.15,17.2759198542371,23.5847155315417));
#1163=CARTESIAN_POINT('',(57.1146833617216,17.2789321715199,23.7177810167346));
#1164=CARTESIAN_POINT('',(57.0161688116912,17.2829907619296,23.8970643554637));
#1165=CARTESIAN_POINT('',(56.9737522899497,17.2842974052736,23.9547837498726));
#1166=CARTESIAN_POINT('',(56.9048222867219,17.2858946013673,24.0253379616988));
#1167=CARTESIAN_POINT('',(56.8844999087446,17.2863167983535,24.0439880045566));
#1168=CARTESIAN_POINT('',(56.8046348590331,17.2878080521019,24.1098623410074));
#1169=CARTESIAN_POINT('',(56.738974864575,17.2887088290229,24.1496530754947));
#1170=CARTESIAN_POINT('',(56.6120949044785,17.2899421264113,24.2041325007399));
#1171=CARTESIAN_POINT('',(56.5522794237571,17.2903486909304,24.22209199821));
#1172=CARTESIAN_POINT('',(56.4528186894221,17.2907456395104,24.2396267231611));
#1173=CARTESIAN_POINT('',(56.4139344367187,17.2908345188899,24.2435528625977));
#1174=CARTESIAN_POINT('',(56.3749361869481,17.2908553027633,24.2444709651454));
#1175=B_SPLINE_CURVE_WITH_KNOTS('',3,(#1161,#1162,#1163,#1164,#1165,#1166,#1167,#1168,#1169,
#1170,#1171,#1172,#1173,#1174),.UNSPECIFIED.,.F.,.F.,(4,2,2,2,2,2,4),(0.,0.32636293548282,0.5,
0.567338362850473,0.75310840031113,0.904711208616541,1.),.UNSPECIFIED.);
#1176=CARTESIAN_POINT('',(56.3749361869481,17.2908553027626,24.2444709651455));
#1177=VERTEX_POINT('',#1176);
#1178=EDGE_CURVE('E370',#1159,#1177,#1175,.T.);
#1179=CARTESIAN_POINT('',(56.3749361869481,17.2908553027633,24.2444709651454));
#1180=CARTESIAN_POINT('',(56.3749626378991,14.5523090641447,24.306465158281));
#1181=CARTESIAN_POINT('',(56.3749971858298,11.8137628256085,24.3684592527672));
#1182=CARTESIAN_POINT('',(56.3750398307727,9.0752165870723,24.4304532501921));
#1183=CARTESIAN_POINT('',(56.3750402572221,9.04783112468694,24.4310731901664));
#1184=CARTESIAN_POINT('',(56.3750406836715,9.02044566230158,24.4316931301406));
#1185=CARTESIAN_POINT('',(56.375041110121,8.99306019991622,24.4323130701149));
#1186=B_SPLINE_CURVE_WITH_KNOTS('',3,(#1179,#1180,#1181,#1182,#1183,#1184,#1185),.UNSPECIFIED.,
.F.,.F.,(4,3,4),(-0.01,0.99,1.),.UNSPECIFIED.);
#1187=EDGE_CURVE('E163',#1177,#696,#1186,.T.);
#1188=ORIENTED_EDGE('',*,*,#1160,.T.);
#1189=ORIENTED_EDGE('',*,*,#1178,.T.);
#1190=ORIENTED_EDGE('',*,*,#1187,.T.);
#1191=ORIENTED_EDGE('',*,*,#697,.F.);
#1192=EDGE_LOOP('',(#1188,#1189,#1190,#1191));
#1193=FACE_BOUND('',#1192,.T.);
#1194=ADVANCED_FACE('F235',(#1193),#1153,.T.);
#1195=CARTESIAN_POINT('',(57.1500000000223,33.6295999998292,57.1500000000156));
#1196=DIRECTION('',(-2.94219527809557E-12,-1.,-2.05842950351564E-12));
#1197=DIRECTION('',(0.974370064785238,-3.32983289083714E-12,0.224951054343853));
#1198=AXIS2_PLACEMENT_3D('',#1195,#1196,#1197);
#1199=CYLINDRICAL_SURFACE('',#1198,47.6250000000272);
#1200=ORIENTED_EDGE('',*,*,#58,.T.);
#1201=DIRECTION('',(0.,-1.,0.));
#1202=VECTOR('',#1201,1.);
#1203=CARTESIAN_POINT('',(17.2083142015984,33.6296,31.2115659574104));
#1204=LINE('',#1203,#1202);
#1205=CARTESIAN_POINT('',(17.2083142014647,25.4000000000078,31.2115659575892));
#1206=VERTEX_POINT('',#1205);
#1207=EDGE_CURVE('E599',#1206,#50,#1204,.T.);
#1208=ORIENTED_EDGE('',*,*,#1207,.F.);
#1209=CARTESIAN_POINT('',(57.1499999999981,25.3999999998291,57.1499999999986));
#1210=DIRECTION('',(-2.94219527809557E-12,-1.,-2.05842950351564E-12));
#1211=DIRECTION('',(0.974370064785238,-3.32983289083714E-12,0.224951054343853));
#1212=AXIS2_PLACEMENT_3D('',#1209,#1210,#1211);
#1213=CIRCLE('',#1212,47.6250000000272);
#1214=CARTESIAN_POINT('',(19.6209878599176,25.4000000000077,27.8291222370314));
#1215=VERTEX_POINT('',#1214);
#1216=EDGE_CURVE('E596',#1206,#1215,#1213,.T.);
#1217=ORIENTED_EDGE('',*,*,#1216,.T.);
#1218=DIRECTION('',(0.,-1.,0.));
#1219=VECTOR('',#1218,1.);
#1220=CARTESIAN_POINT('',(19.6209878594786,33.6296,27.8291222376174));
#1221=LINE('',#1220,#1219);
#1222=EDGE_CURVE('E593',#32,#1215,#1221,.F.);
#1223=ORIENTED_EDGE('',*,*,#1222,.F.);
#1224=EDGE_LOOP('',(#1200,#1208,#1217,#1223));
#1225=FACE_BOUND('',#1224,.T.);
#1226=ADVANCED_FACE('F246',(#1225),#1199,.T.);
#1227=CARTESIAN_POINT('',(22.7978712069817,33.6296,30.2092155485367));
#1228=DIRECTION('',(0.,-1.,0.));
#1229=DIRECTION('',(0.974370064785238,0.,0.224951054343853));
#1230=AXIS2_PLACEMENT_3D('',#1227,#1228,#1229);
#1231=CYLINDRICAL_SURFACE('',#1230,3.96956319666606);
#1232=ORIENTED_EDGE('',*,*,#33,.T.);
#1233=ORIENTED_EDGE('',*,*,#1222,.T.);
#1234=CARTESIAN_POINT('',(22.7978712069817,25.4,30.2092155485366));
#1235=DIRECTION('',(0.,-1.,0.));
#1236=DIRECTION('',(0.974370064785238,0.,0.224951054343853));
#1237=AXIS2_PLACEMENT_3D('',#1234,#1235,#1236);
#1238=CIRCLE('',#1237,3.96956319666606);
#1239=CARTESIAN_POINT('',(25.8758232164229,25.4000000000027,32.71593519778));
#1240=VERTEX_POINT('',#1239);
#1241=EDGE_CURVE('E528',#1215,#1240,#1238,.T.);
#1242=ORIENTED_EDGE('',*,*,#1241,.T.);
#1243=DIRECTION('',(0.,-1.,0.));
#1244=VECTOR('',#1243,1.);
#1245=CARTESIAN_POINT('',(25.8758232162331,33.6296,32.715935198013));
#1246=LINE('',#1245,#1244);
#1247=EDGE_CURVE('E525',#1240,#30,#1246,.T.);
#1248=ORIENTED_EDGE('',*,*,#1247,.T.);
#1249=EDGE_LOOP('',(#1232,#1233,#1242,#1248));
#1250=FACE_BOUND('',#1249,.T.);
#1251=ADVANCED_FACE('F670',(#1250),#1231,.T.);
#1252=CARTESIAN_POINT('',(57.15,25.4,57.15));
#1253=DIRECTION('',(0.,-1.,0.));
#1254=DIRECTION('',(-0.224951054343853,0.,0.974370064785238));
#1255=AXIS2_PLACEMENT_3D('',#1252,#1253,#1254);
#1256=PLANE('',#1255);
#1257=ORIENTED_EDGE('',*,*,#1216,.F.);
#1258=CARTESIAN_POINT('',(20.3938022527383,25.4,33.5932808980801));
#1259=DIRECTION('',(0.,-1.,0.));
#1260=DIRECTION('',(-0.224951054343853,0.,0.974370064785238));
#1261=AXIS2_PLACEMENT_3D('',#1258,#1259,#1260);
#1262=CIRCLE('',#1261,3.97742381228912);
#1263=CARTESIAN_POINT('',(23.8652618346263,25.4000000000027,35.5346382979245));
#1264=VERTEX_POINT('',#1263);
#1265=EDGE_CURVE('E522',#1264,#1206,#1262,.T.);
#1266=ORIENTED_EDGE('',*,*,#1265,.F.);
#1267=CARTESIAN_POINT('',(57.1500000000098,25.4000000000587,57.1500000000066));
#1268=DIRECTION('',(1.21401796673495E-12,-1.,8.47143766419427E-13));
#1269=DIRECTION('',(0.974370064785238,1.37346864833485E-12,0.224951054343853));
#1270=AXIS2_PLACEMENT_3D('',#1267,#1268,#1269);
#1271=CIRCLE('',#1270,39.6874999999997);
#1272=EDGE_CURVE('E516',#1264,#1240,#1271,.T.);
#1273=ORIENTED_EDGE('',*,*,#1272,.T.);
#1274=ORIENTED_EDGE('',*,*,#1241,.F.);
#1275=EDGE_LOOP('',(#1257,#1266,#1273,#1274));
#1276=FACE_BOUND('',#1275,.T.);
#1277=ADVANCED_FACE('F673',(#1276),#1256,.F.);
#1278=CARTESIAN_POINT('',(20.3938022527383,33.6296,33.5932808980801));
#1279=DIRECTION('',(0.,-1.,0.));
#1280=DIRECTION('',(-0.224951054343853,0.,0.974370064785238));
#1281=AXIS2_PLACEMENT_3D('',#1278,#1279,#1280);
#1282=CYLINDRICAL_SURFACE('',#1281,3.97742381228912);
#1283=ORIENTED_EDGE('',*,*,#51,.T.);
#1284=DIRECTION('',(1.21401796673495E-12,-1.,8.47143766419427E-13));
#1285=VECTOR('',#1284,1.);
#1286=CARTESIAN_POINT('',(23.8652618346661,33.6296000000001,35.5346382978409));
#1287=LINE('',#1286,#1285);
#1288=EDGE_CURVE('E511',#41,#1264,#1287,.F.);
#1289=ORIENTED_EDGE('',*,*,#1288,.T.);
#1290=ORIENTED_EDGE('',*,*,#1265,.T.);
#1291=ORIENTED_EDGE('',*,*,#1207,.T.);
#1292=EDGE_LOOP('',(#1283,#1289,#1290,#1291));
#1293=FACE_BOUND('',#1292,.T.);
#1294=ADVANCED_FACE('F676',(#1293),#1282,.T.);
#1295=CARTESIAN_POINT('',(57.1499999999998,33.6296000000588,57.1499999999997));
#1296=DIRECTION('',(1.21401796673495E-12,-1.,8.47143766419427E-13));
#1297=DIRECTION('',(0.974370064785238,1.37346864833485E-12,0.224951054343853));
#1298=AXIS2_PLACEMENT_3D('',#1295,#1296,#1297);
#1299=CYLINDRICAL_SURFACE('',#1298,39.6874999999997);
#1300=ORIENTED_EDGE('',*,*,#42,.T.);
#1301=ORIENTED_EDGE('',*,*,#1247,.F.);
#1302=ORIENTED_EDGE('',*,*,#1272,.F.);
#1303=ORIENTED_EDGE('',*,*,#1288,.F.);
#1304=EDGE_LOOP('',(#1300,#1301,#1302,#1303));
#1305=FACE_BOUND('',#1304,.T.);
#1306=ADVANCED_FACE('F464',(#1305),#1299,.F.);
#1307=CARTESIAN_POINT('',(12.6110486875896,21.9456,40.2851714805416));
#1308=DIRECTION('',(-0.22495105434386,0.,0.974370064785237));
#1309=DIRECTION('',(-0.974370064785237,0.,-0.22495105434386));
#1310=AXIS2_PLACEMENT_3D('',#1307,#1308,#1309);
#1311=PLANE('',#1310);
#1312=ORIENTED_EDGE('',*,*,#117,.T.);
#1313=ORIENTED_EDGE('',*,*,#526,.F.);
#1314=ORIENTED_EDGE('',*,*,#418,.T.);
#1315=EDGE_LOOP('',(#1312,#1313,#1314));
#1316=FACE_BOUND('',#1315,.T.);
#1317=ADVANCED_FACE('F285',(#1316),#1311,.F.);
#1318=CARTESIAN_POINT('',(61.5165836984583,17.9717910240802,9.72560151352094));
#1319=DIRECTION('',(0.974370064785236,0.,0.224951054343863));
#1320=DIRECTION('',(-0.224951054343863,0.,0.974370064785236));
#1321=AXIS2_PLACEMENT_3D('',#1318,#1319,#1320);
#1322=PLANE('',#1321);
#1323=ORIENTED_EDGE('',*,*,#726,.F.);
#1324=ORIENTED_EDGE('',*,*,#195,.T.);
#1325=ORIENTED_EDGE('',*,*,#626,.T.);
#1326=EDGE_LOOP('',(#1323,#1324,#1325));
#1327=FACE_BOUND('',#1326,.T.);
#1328=ADVANCED_FACE('F288',(#1327),#1322,.F.);
#1329=CARTESIAN_POINT('',(56.35625,21.15185,9.53105648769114));
#1330=DIRECTION('',(0.,0.,1.));
#1331=DIRECTION('',(-1.,0.,0.));
#1332=AXIS2_PLACEMENT_3D('',#1329,#1330,#1331);
#1333=CYLINDRICAL_SURFACE('',#1332,0.793749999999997);
#1334=CARTESIAN_POINT('',(57.15,21.15185,19.4824256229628));
#1335=CARTESIAN_POINT('',(57.15,21.3596532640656,19.4824256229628));
#1336=CARTESIAN_POINT('',(57.0644551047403,21.5661769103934,19.4824256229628));
#1337=CARTESIAN_POINT('',(56.7705769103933,21.8600551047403,19.4824256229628));
#1338=CARTESIAN_POINT('',(56.5640532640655,21.9456,19.4824256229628));
#1339=CARTESIAN_POINT('',(56.35625,21.9456,19.4824256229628));
#1340=B_SPLINE_CURVE_WITH_KNOTS('',3,(#1334,#1335,#1336,#1337,#1338,#1339),.UNSPECIFIED.,.F.,
.F.,(4,2,4),(0.,0.5,1.),.UNSPECIFIED.);
#1341=CARTESIAN_POINT('',(57.15,21.15185,19.4824256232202));
#1342=VERTEX_POINT('',#1341);
#1343=EDGE_CURVE('E347',#169,#1342,#1340,.F.);
#1344=ORIENTED_EDGE('',*,*,#1343,.T.);
#1345=DIRECTION('',(0.,0.,1.));
#1346=VECTOR('',#1345,1.);
#1347=CARTESIAN_POINT('',(57.15,21.15185,9.53105648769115));
#1348=LINE('',#1347,#1346);
#1349=EDGE_CURVE('E437',#1342,#657,#1348,.F.);
#1350=ORIENTED_EDGE('',*,*,#1349,.T.);
#1351=ORIENTED_EDGE('',*,*,#658,.T.);
#1352=ORIENTED_EDGE('',*,*,#178,.T.);
#1353=EDGE_LOOP('',(#1344,#1350,#1351,#1352));
#1354=FACE_BOUND('',#1353,.T.);
#1355=ADVANCED_FACE('F320',(#1354),#1333,.T.);
#1356=CARTESIAN_POINT('',(56.35625,21.9456,19.4824256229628));
#1357=CARTESIAN_POINT('',(56.3573493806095,21.9456,19.7955694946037));
#1358=CARTESIAN_POINT('',(56.3584826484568,21.9144236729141,20.1117315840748));
#1359=CARTESIAN_POINT('',(56.3614331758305,21.7523565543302,20.9176023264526));
#1360=CARTESIAN_POINT('',(56.3632342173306,21.5750568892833,21.3925141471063));
#1361=CARTESIAN_POINT('',(56.3676978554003,20.927155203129,22.5352400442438));
#1362=CARTESIAN_POINT('',(56.3701682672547,20.3489817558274,23.1316699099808));
#1363=CARTESIAN_POINT('',(56.3737883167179,18.945304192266,23.9855623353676));
#1364=CARTESIAN_POINT('',(56.3748541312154,18.1174045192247,24.2257615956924));
#1365=CARTESIAN_POINT('',(56.3749361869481,17.2908553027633,24.2444709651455));
#1366=CARTESIAN_POINT('',(56.5640532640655,21.9456,19.4824256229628));
#1367=CARTESIAN_POINT('',(56.5649694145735,21.9453121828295,19.7955694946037));
#1368=CARTESIAN_POINT('',(56.5659131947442,21.9138398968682,20.1116737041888));
#1369=CARTESIAN_POINT('',(56.5683686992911,21.7510494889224,20.9172442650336));
#1370=CARTESIAN_POINT('',(56.569865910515,21.5733563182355,21.3918258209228));
#1371=CARTESIAN_POINT('',(56.5735728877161,20.9247598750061,22.5334408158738));
#1372=CARTESIAN_POINT('',(56.5756206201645,20.3465197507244,23.1289494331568));
#1373=CARTESIAN_POINT('',(56.5786188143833,18.9435582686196,23.9813248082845));
#1374=CARTESIAN_POINT('',(56.5795001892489,18.1164593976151,24.2209838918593));
#1375=CARTESIAN_POINT('',(56.579568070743,17.2907462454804,24.2396534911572));
#1376=CARTESIAN_POINT('',(56.7705769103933,21.8600551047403,19.4824256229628));
#1377=CARTESIAN_POINT('',(56.7711969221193,21.8596386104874,19.7899468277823));
#1378=CARTESIAN_POINT('',(56.7718354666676,21.828594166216,20.1003483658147));
#1379=CARTESIAN_POINT('',(56.7734963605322,21.6683922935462,20.8913154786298));
#1380=CARTESIAN_POINT('',(56.7745086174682,21.493708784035,21.3572228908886));
#1381=CARTESIAN_POINT('',(56.7770138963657,20.8564418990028,22.4778266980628));
#1382=CARTESIAN_POINT('',(56.7783967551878,20.2885586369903,23.0622182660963));
#1383=CARTESIAN_POINT('',(56.7804208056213,18.9111298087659,23.8985911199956));
#1384=CARTESIAN_POINT('',(56.7810154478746,18.0992576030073,24.1336990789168));
#1385=CARTESIAN_POINT('',(56.7810612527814,17.2887623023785,24.1520151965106));
#1386=CARTESIAN_POINT('',(57.0644551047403,21.5661769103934,19.4824256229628));
#1387=CARTESIAN_POINT('',(57.0646124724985,21.5658160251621,19.7706308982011));
#1388=CARTESIAN_POINT('',(57.0647744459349,21.5367526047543,20.0615417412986));
#1389=CARTESIAN_POINT('',(57.0651954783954,21.3866913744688,20.8028588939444));
#1390=CARTESIAN_POINT('',(57.0654518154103,21.2230247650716,21.239537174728));
#1391=CARTESIAN_POINT('',(57.0660856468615,20.6258727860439,22.2898731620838));
#1392=CARTESIAN_POINT('',(57.0664348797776,20.093680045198,22.8376573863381));
#1393=CARTESIAN_POINT('',(57.0669456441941,18.8027289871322,23.621660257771));
#1394=CARTESIAN_POINT('',(57.0670954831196,18.0417882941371,23.842059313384));
#1395=CARTESIAN_POINT('',(57.0671070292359,17.2821342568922,23.8592292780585));
#1396=CARTESIAN_POINT('',(57.15,21.3596532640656,19.4824256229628));
#1397=CARTESIAN_POINT('',(57.15,21.359470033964,19.7570565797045));
#1398=CARTESIAN_POINT('',(57.15,21.3319411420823,20.0342981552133));
#1399=CARTESIAN_POINT('',(57.15,21.1893538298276,20.7408679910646));
#1400=CARTESIAN_POINT('',(57.15,21.033618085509,21.1571640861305));
#1401=CARTESIAN_POINT('',(57.15,20.4649894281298,22.1586520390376));
#1402=CARTESIAN_POINT('',(57.15,19.9579092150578,22.6811514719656));
#1403=CARTESIAN_POINT('',(57.15,18.7273863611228,23.4290766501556));
#1404=CARTESIAN_POINT('',(57.15,18.0018542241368,23.6393968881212));
#1405=CARTESIAN_POINT('',(57.15,17.2775286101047,23.6557803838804));
#1406=CARTESIAN_POINT('',(57.15,21.15185,19.4824256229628));
#1407=CARTESIAN_POINT('',(57.15,21.15185,19.7433981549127));
#1408=CARTESIAN_POINT('',(57.15,21.1258697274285,20.0068866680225));
#1409=CARTESIAN_POINT('',(57.15,20.9908137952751,20.6784985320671));
#1410=CARTESIAN_POINT('',(57.15,20.8430640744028,21.0742912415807));
#1411=CARTESIAN_POINT('',(57.15,20.3031460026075,22.0266455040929));
#1412=CARTESIAN_POINT('',(57.15,19.8213347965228,22.5237174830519));
#1413=CARTESIAN_POINT('',(57.15,18.651603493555,23.2353643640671));
#1414=CARTESIAN_POINT('',(57.15,17.9616870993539,23.4355514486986));
#1415=CARTESIAN_POINT('',(57.15,17.2728960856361,23.4511442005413));
#1416=B_SPLINE_SURFACE_WITH_KNOTS('',3,3,((#1356,#1357,#1358,#1359,#1360,#1361,#1362,#1363,
#1364,#1365),(#1366,#1367,#1368,#1369,#1370,#1371,#1372,#1373,#1374,#1375),(#1376,#1377,#1378,
#1379,#1380,#1381,#1382,#1383,#1384,#1385),(#1386,#1387,#1388,#1389,#1390,#1391,#1392,#1393,
#1394,#1395),(#1396,#1397,#1398,#1399,#1400,#1401,#1402,#1403,#1404,#1405),(#1406,#1407,#1408,
#1409,#1410,#1411,#1412,#1413,#1414,#1415)),.UNSPECIFIED.,.F.,.F.,.F.,(4,2,4),(4,2,2,2,4),(0.,
0.5,1.),(-0.610675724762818,-0.532383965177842,-0.407117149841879,-0.206690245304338,0.),.UNSPECIFIED.);
#1417=CARTESIAN_POINT('',(56.35625,21.9456,19.4824256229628));
#1418=CARTESIAN_POINT('',(56.3565185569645,21.9455971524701,19.5589197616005));
#1419=CARTESIAN_POINT('',(56.3567884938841,21.9437397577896,19.6354125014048));
#1420=CARTESIAN_POINT('',(56.3573314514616,21.9363338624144,19.788490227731));
#1421=CARTESIAN_POINT('',(56.3576044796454,21.9307723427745,19.8650745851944));
#1422=CARTESIAN_POINT('',(56.3581526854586,21.9159590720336,20.018068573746));
#1423=CARTESIAN_POINT('',(56.3584278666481,21.9066986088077,20.0944773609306));
#1424=CARTESIAN_POINT('',(56.3589794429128,21.8844776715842,20.2468527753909));
#1425=CARTESIAN_POINT('',(56.359255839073,21.8715126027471,20.322818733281));
#1426=CARTESIAN_POINT('',(56.3598086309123,21.8419141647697,20.4739617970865));
#1427=CARTESIAN_POINT('',(56.3600850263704,21.8252840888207,20.5491395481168));
#1428=CARTESIAN_POINT('',(56.3606367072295,21.78845656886,20.6984288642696));
#1429=CARTESIAN_POINT('',(56.3609119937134,21.7682675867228,20.772542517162));
#1430=CARTESIAN_POINT('',(56.3614609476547,21.7243559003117,20.919598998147));
#1431=CARTESIAN_POINT('',(56.3617346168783,21.7006383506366,20.9925433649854));
#1432=CARTESIAN_POINT('',(56.3622798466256,21.6497154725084,21.1371606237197));
#1433=CARTESIAN_POINT('',(56.362551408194,21.6225120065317,21.2088341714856));
#1434=CARTESIAN_POINT('',(56.3630919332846,21.5646607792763,21.3508094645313));
#1435=CARTESIAN_POINT('',(56.3633608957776,21.5340117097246,21.421110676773));
#1436=CARTESIAN_POINT('',(56.3638957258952,21.4693094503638,21.5602389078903));
#1437=CARTESIAN_POINT('',(56.3641615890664,21.4352519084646,21.6290639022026));
#1438=CARTESIAN_POINT('',(56.3646897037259,21.3637956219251,21.7651321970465));
#1439=CARTESIAN_POINT('',(56.3649519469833,21.3263903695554,21.8323720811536));
#1440=CARTESIAN_POINT('',(56.3654714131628,21.2483352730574,21.964932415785));
#1441=CARTESIAN_POINT('',(56.3657286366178,21.2076857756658,22.0302530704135));
#1442=CARTESIAN_POINT('',(56.3662371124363,21.123283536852,22.1587960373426));
#1443=CARTESIAN_POINT('',(56.3664883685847,21.0795328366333,22.2220196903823));
#1444=CARTESIAN_POINT('',(56.3669842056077,20.9890443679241,22.3462502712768));
#1445=CARTESIAN_POINT('',(56.3672287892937,20.9423078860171,22.4072581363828));
#1446=CARTESIAN_POINT('',(56.3677105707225,20.845963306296,22.5269379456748));
#1447=CARTESIAN_POINT('',(56.3679477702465,20.7963559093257,22.5856104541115));
#1448=CARTESIAN_POINT('',(56.3684140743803,20.6943849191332,22.7005005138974));
#1449=CARTESIAN_POINT('',(56.3686431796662,20.6420215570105,22.756718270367));
#1450=CARTESIAN_POINT('',(56.3690925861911,20.5346539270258,22.8665797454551));
#1451=CARTESIAN_POINT('',(56.3693128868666,20.4796494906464,22.9202232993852));
#1452=CARTESIAN_POINT('',(56.3697439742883,20.3671148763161,23.0248171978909));
#1453=CARTESIAN_POINT('',(56.3699547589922,20.3095841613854,23.0757669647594));
#1454=CARTESIAN_POINT('',(56.3703661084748,20.1921123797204,23.1748545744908));
#1455=CARTESIAN_POINT('',(56.3705666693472,20.1321704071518,23.2229913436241));
#1456=CARTESIAN_POINT('',(56.3709568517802,20.0099905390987,23.3163327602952));
#1457=CARTESIAN_POINT('',(56.3711464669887,19.9477513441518,23.3615357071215));
#1458=CARTESIAN_POINT('',(56.3715140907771,19.8210950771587,23.4488952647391));
#1459=CARTESIAN_POINT('',(56.3716920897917,19.756676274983,23.4910493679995));
#1460=CARTESIAN_POINT('',(56.3720355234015,19.625803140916,23.5721519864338));
#1461=CARTESIAN_POINT('',(56.3722009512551,19.559347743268,23.611098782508));
#1462=CARTESIAN_POINT('',(56.3725182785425,19.4246176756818,23.6856495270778));
#1463=CARTESIAN_POINT('',(56.3726701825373,19.3563436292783,23.7212546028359));
#1464=CARTESIAN_POINT('',(56.3729602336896,19.2181681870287,23.7890885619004));
#1465=CARTESIAN_POINT('',(56.3730983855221,19.1482673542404,23.821318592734));
#1466=CARTESIAN_POINT('',(56.373360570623,19.0070199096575,23.8823550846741));
#1467=CARTESIAN_POINT('',(56.3734846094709,18.9356738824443,23.9111628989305));
#1468=CARTESIAN_POINT('',(56.3737182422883,18.791719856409,23.9653112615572));
#1469=CARTESIAN_POINT('',(56.3738278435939,18.7191125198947,23.9906535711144));
#1470=CARTESIAN_POINT('',(56.3740322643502,18.572819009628,24.0378259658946));
#1471=CARTESIAN_POINT('',(56.3741270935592,18.4991335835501,24.0596583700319));
#1472=CARTESIAN_POINT('',(56.3743016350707,18.3508672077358,24.0997661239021));
#1473=CARTESIAN_POINT('',(56.3743813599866,18.2762870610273,24.118044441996));
#1474=CARTESIAN_POINT('',(56.3745253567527,18.1264145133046,24.1509990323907));
#1475=CARTESIAN_POINT('',(56.3745896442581,18.0511229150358,24.1656789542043));
#1476=CARTESIAN_POINT('',(56.3747024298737,17.9000109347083,24.1913917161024));
#1477=CARTESIAN_POINT('',(56.3747509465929,17.8241912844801,24.2024288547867));
#1478=CARTESIAN_POINT('',(56.3748318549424,17.6722062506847,24.2208111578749));
#1479=CARTESIAN_POINT('',(56.3748642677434,17.5960414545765,24.2281611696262));
#1480=CARTESIAN_POINT('',(56.374912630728,17.4435510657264,24.2391239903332));
#1481=CARTESIAN_POINT('',(56.3749286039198,17.3672258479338,24.242742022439));
#1482=CARTESIAN_POINT('',(56.3749361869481,17.2908553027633,24.2444709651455));
#1483=B_SPLINE_CURVE_WITH_KNOTS('',3,(#1417,#1418,#1419,#1420,#1421,#1422,#1423,#1424,#1425,
#1426,#1427,#1428,#1429,#1430,#1431,#1432,#1433,#1434,#1435,#1436,#1437,#1438,#1439,#1440,#1441,
#1442,#1443,#1444,#1445,#1446,#1447,#1448,#1449,#1450,#1451,#1452,#1453,#1454,#1455,#1456,#1457,
#1458,#1459,#1460,#1461,#1462,#1463,#1464,#1465,#1466,#1467,#1468,#1469,#1470,#1471,#1472,#1473,
#1474,#1475,#1476,#1477,#1478,#1479,#1480,#1481,#1482),.UNSPECIFIED.,.F.,.F.,(4,2,2,2,2,2,2,2,2,
2,2,2,2,2,2,2,2,2,2,2,2,2,2,2,2,2,2,2,2,2,2,2,4),(0.,0.229459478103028,0.45972972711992,
0.690545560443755,0.921648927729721,1.15254547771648,1.38290026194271,1.61292178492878,
1.84282091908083,2.07280764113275,2.30309186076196,2.53383388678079,2.76455128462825,
2.99511821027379,3.22558644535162,3.45599865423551,3.68639157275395,3.91679921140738,
4.14725606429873,4.37780031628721,4.60847704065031,4.83934137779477,5.070328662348,
5.30123774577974,5.53206806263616,5.76280680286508,5.99342784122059,6.22389588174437,
6.45417060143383,6.68421079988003,6.91397856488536,7.14344346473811,7.37258677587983),.UNSPECIFIED.);
#1484=EDGE_CURVE('E359',#169,#1177,#1483,.T.);
#1485=CARTESIAN_POINT('',(57.15,17.2728960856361,23.4511442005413));
#1486=CARTESIAN_POINT('',(57.15,17.9616870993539,23.4355514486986));
#1487=CARTESIAN_POINT('',(57.15,18.651603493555,23.2353643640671));
#1488=CARTESIAN_POINT('',(57.15,19.8213347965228,22.5237174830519));
#1489=CARTESIAN_POINT('',(57.15,20.3031460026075,22.0266455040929));
#1490=CARTESIAN_POINT('',(57.15,20.8430640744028,21.0742912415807));
#1491=CARTESIAN_POINT('',(57.15,20.9908137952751,20.6784985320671));
#1492=CARTESIAN_POINT('',(57.15,21.1258697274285,20.0068866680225));
#1493=CARTESIAN_POINT('',(57.15,21.15185,19.7433981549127));
#1494=CARTESIAN_POINT('',(57.15,21.15185,19.4824256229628));
#1495=B_SPLINE_CURVE_WITH_KNOTS('',3,(#1485,#1486,#1487,#1488,#1489,#1490,#1491,#1492,#1493,
#1494),.UNSPECIFIED.,.F.,.F.,(4,2,2,2,4),(-0.610675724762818,-0.40398547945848,
-0.203558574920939,-0.0782917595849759,0.),.UNSPECIFIED.);
#1496=EDGE_CURVE('E381',#1342,#1159,#1495,.F.);
#1497=ORIENTED_EDGE('',*,*,#1343,.F.);
#1498=ORIENTED_EDGE('',*,*,#1484,.T.);
#1499=ORIENTED_EDGE('',*,*,#1178,.F.);
#1500=ORIENTED_EDGE('',*,*,#1496,.F.);
#1501=EDGE_LOOP('',(#1497,#1498,#1499,#1500));
#1502=FACE_BOUND('',#1501,.T.);
#1503=ADVANCED_FACE('F324',(#1502),#1416,.F.);
#1504=CARTESIAN_POINT('',(57.15,17.1831,57.15));
#1505=DIRECTION('',(0.,1.,0.));
#1506=DIRECTION('',(0.224951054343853,0.,-0.974370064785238));
#1507=AXIS2_PLACEMENT_3D('',#1504,#1505,#1506);
#1508=TOROIDAL_SURFACE('',#1507,37.6759365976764,4.76250000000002);
#1509=ORIENTED_EDGE('',*,*,#143,.T.);
#1510=CARTESIAN_POINT('',(27.9144720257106,17.2908553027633,42.0285427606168));
#1511=CARTESIAN_POINT('',(27.9129213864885,17.3672258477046,42.0277780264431));
#1512=CARTESIAN_POINT('',(27.9096765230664,17.4435510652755,42.0261776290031));
#1513=CARTESIAN_POINT('',(27.8998444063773,17.5960414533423,42.0213283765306));
#1514=CARTESIAN_POINT('',(27.893252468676,17.6722062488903,42.018077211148));
#1515=CARTESIAN_POINT('',(27.8767660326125,17.8241912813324,42.0099462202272));
#1516=CARTESIAN_POINT('',(27.8668671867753,17.9000109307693,42.0050642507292));
#1517=CARTESIAN_POINT('',(27.8438061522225,18.0511229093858,41.9936911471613));
#1518=CARTESIAN_POINT('',(27.8306401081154,18.1264145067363,41.9871981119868));
#1519=CARTESIAN_POINT('',(27.8010838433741,18.2762870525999,41.9726223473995));
#1520=CARTESIAN_POINT('',(27.7846903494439,18.3508671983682,41.9645380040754));
#1521=CARTESIAN_POINT('',(27.7487182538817,18.4991335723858,41.946799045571));
#1522=CARTESIAN_POINT('',(27.7291369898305,18.5728189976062,41.9371431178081));
#1523=CARTESIAN_POINT('',(27.6868283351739,18.7191125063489,41.9162803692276));
#1524=CARTESIAN_POINT('',(27.6640988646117,18.7917198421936,41.9050725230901));
#1525=CARTESIAN_POINT('',(27.6155330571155,18.9356738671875,41.8811254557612));
#1526=CARTESIAN_POINT('',(27.5896951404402,19.0070198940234,41.8683854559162));
#1527=CARTESIAN_POINT('',(27.534950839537,19.1482673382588,41.8413931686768));
#1528=CARTESIAN_POINT('',(27.5060432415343,19.2181681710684,41.8271402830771));
#1529=CARTESIAN_POINT('',(27.4452016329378,19.356343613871,41.7971431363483));
#1530=CARTESIAN_POINT('',(27.4132665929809,19.4246176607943,41.7813983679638));
#1531=CARTESIAN_POINT('',(27.3463999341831,19.5593477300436,41.7484322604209));
#1532=CARTESIAN_POINT('',(27.3114673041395,19.6258031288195,41.7312104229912));
#1533=CARTESIAN_POINT('',(27.2387233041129,19.7566762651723,41.6953486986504));
#1534=CARTESIAN_POINT('',(27.2009134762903,19.8210950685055,41.6767095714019));
#1535=CARTESIAN_POINT('',(27.1225563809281,19.9477513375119,41.6380832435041));
#1536=CARTESIAN_POINT('',(27.0820113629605,20.0099905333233,41.6180971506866));
#1537=CARTESIAN_POINT('',(26.9982876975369,20.1321704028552,41.5768282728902));
#1538=CARTESIAN_POINT('',(26.9551105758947,20.1921123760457,41.5555462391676));
#1539=CARTESIAN_POINT('',(26.8662315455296,20.3095841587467,41.5117393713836));
#1540=CARTESIAN_POINT('',(26.820530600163,20.3671148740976,41.4892150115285));
#1541=CARTESIAN_POINT('',(26.7267112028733,20.4796494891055,41.4429766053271));
#1542=CARTESIAN_POINT('',(26.6785932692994,20.5346539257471,41.4192628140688));
#1543=CARTESIAN_POINT('',(26.5800474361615,20.6420215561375,41.370698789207));
#1544=CARTESIAN_POINT('',(26.5296196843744,20.6943849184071,41.345848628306));
#1545=CARTESIAN_POINT('',(26.4265615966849,20.7963559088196,41.2950650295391));
#1546=CARTESIAN_POINT('',(26.3739310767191,20.8459633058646,41.2691315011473));
#1547=CARTESIAN_POINT('',(26.2665747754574,20.9423078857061,41.2162343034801));
#1548=CARTESIAN_POINT('',(26.2118484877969,20.9890443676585,41.1892703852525));
#1549=CARTESIAN_POINT('',(26.1004081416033,21.079532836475,41.134365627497));
#1550=CARTESIAN_POINT('',(26.0436932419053,21.1232835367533,41.1064243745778));
#1551=CARTESIAN_POINT('',(25.9283824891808,21.2076857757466,41.0496178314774));
#1552=CARTESIAN_POINT('',(25.8697854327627,21.2483352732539,41.0207519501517));
#1553=CARTESIAN_POINT('',(25.7508687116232,21.3263903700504,40.9621744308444));
#1554=CARTESIAN_POINT('',(25.6905488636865,21.3637956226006,40.9324627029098));
#1555=CARTESIAN_POINT('',(25.568483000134,21.4352519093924,40.8723396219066));
#1556=CARTESIAN_POINT('',(25.5067400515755,21.4693094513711,40.8419297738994));
#1557=CARTESIAN_POINT('',(25.3819268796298,21.5340117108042,40.7804592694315));
#1558=CARTESIAN_POINT('',(25.3188584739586,21.5646607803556,40.7493995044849));
#1559=CARTESIAN_POINT('',(25.1914888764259,21.6225120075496,40.686675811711));
#1560=CARTESIAN_POINT('',(25.1271881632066,21.6497154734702,40.6550121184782));
#1561=CARTESIAN_POINT('',(24.9974460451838,21.7006383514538,40.5911260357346));
#1562=CARTESIAN_POINT('',(24.9320040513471,21.7243559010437,40.5589033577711));
#1563=CARTESIAN_POINT('',(24.8000712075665,21.7682675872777,40.4939446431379));
#1564=CARTESIAN_POINT('',(24.7335789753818,21.7884565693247,40.4612079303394));
#1565=CARTESIAN_POINT('',(24.5996404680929,21.8252840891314,40.3952679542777));
#1566=CARTESIAN_POINT('',(24.5321923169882,21.8419141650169,40.3620637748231));
#1567=CARTESIAN_POINT('',(24.3965881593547,21.8715126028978,40.2953101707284));
#1568=CARTESIAN_POINT('',(24.3284315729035,21.8844776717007,40.261760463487));
#1569=CARTESIAN_POINT('',(24.1917192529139,21.9066986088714,40.1944677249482));
#1570=CARTESIAN_POINT('',(24.1231641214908,21.9159590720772,40.1607249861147));
#1571=CARTESIAN_POINT('',(23.9858943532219,21.9307723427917,40.0931641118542));
#1572=CARTESIAN_POINT('',(23.9171804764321,21.9363338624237,40.0593463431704));
#1573=CARTESIAN_POINT('',(23.7798331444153,21.9437397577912,39.9917534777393));
#1574=CARTESIAN_POINT('',(23.7112002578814,21.9455971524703,39.9579786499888));
#1575=CARTESIAN_POINT('',(23.6425655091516,21.9456,39.9242044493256));
#1576=B_SPLINE_CURVE_WITH_KNOTS('',3,(#1510,#1511,#1512,#1513,#1514,#1515,#1516,#1517,#1518,
#1519,#1520,#1521,#1522,#1523,#1524,#1525,#1526,#1527,#1528,#1529,#1530,#1531,#1532,#1533,#1534,
#1535,#1536,#1537,#1538,#1539,#1540,#1541,#1542,#1543,#1544,#1545,#1546,#1547,#1548,#1549,#1550,
#1551,#1552,#1553,#1554,#1555,#1556,#1557,#1558,#1559,#1560,#1561,#1562,#1563,#1564,#1565,#1566,
#1567,#1568,#1569,#1570,#1571,#1572,#1573,#1574,#1575),.UNSPECIFIED.,.F.,.F.,(4,2,2,2,2,2,2,2,2,
2,2,2,2,2,2,2,2,2,2,2,2,2,2,2,2,2,2,2,2,2,2,2,4),(0.,0.229143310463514,0.45860820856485,
0.688375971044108,0.918416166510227,1.14869088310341,1.37915892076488,1.60977995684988,
1.84051869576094,2.07134901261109,2.30225809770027,2.53324538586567,2.76410972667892,
2.99478645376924,3.22533070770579,3.45578756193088,3.68619520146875,3.91658812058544,
4.14700032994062,4.37746856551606,4.6080354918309,4.83875289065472,5.06949491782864,
5.29977913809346,5.52976586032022,5.75966499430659,5.98968651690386,6.22004130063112,
6.45093785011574,6.68204121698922,6.91285705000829,7.14312729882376,7.37258677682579),.UNSPECIFIED.);
#1577=EDGE_CURVE('E154',#1023,#133,#1576,.T.);
#1578=ORIENTED_EDGE('',*,*,#1577,.F.);
#1579=CARTESIAN_POINT('',(57.1499999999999,17.2908553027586,57.15));
#1580=DIRECTION('',(0.,1.,0.));
#1581=DIRECTION('',(0.224951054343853,0.,-0.974370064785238));
#1582=AXIS2_PLACEMENT_3D('',#1579,#1580,#1581);
#1583=CIRCLE('',#1582,32.9146557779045);
#1584=EDGE_CURVE('E429',#1177,#1023,#1583,.T.);
#1585=ORIENTED_EDGE('',*,*,#1584,.F.);
#1586=ORIENTED_EDGE('',*,*,#1484,.F.);
#1587=ORIENTED_EDGE('',*,*,#170,.T.);
#1588=CARTESIAN_POINT('',(38.1573316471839,21.9415083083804,24.8402308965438));
#1589=CARTESIAN_POINT('',(38.2468467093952,21.9378142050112,24.8909378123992));
#1590=CARTESIAN_POINT('',(38.3371344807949,21.9316588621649,24.9400331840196));
#1591=CARTESIAN_POINT('',(38.5189742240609,21.9147816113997,25.0349010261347));
#1592=CARTESIAN_POINT('',(38.6105256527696,21.9040616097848,25.0806748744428));
#1593=CARTESIAN_POINT('',(38.8861966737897,21.8656595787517,25.2126529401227));
#1594=CARTESIAN_POINT('',(39.0718903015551,21.8317081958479,25.2938285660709));
#1595=CARTESIAN_POINT('',(39.4429028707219,21.7505374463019,25.4414006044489));
#1596=CARTESIAN_POINT('',(39.6281892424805,21.7035146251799,25.507991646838));
#1597=CARTESIAN_POINT('',(40.0000391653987,21.5986230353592,25.6281254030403));
#1598=CARTESIAN_POINT('',(40.1866036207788,21.5407456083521,25.6816576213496));
#1599=CARTESIAN_POINT('',(40.6201151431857,21.3967651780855,25.7911236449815));
#1600=CARTESIAN_POINT('',(40.867226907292,21.3075646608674,25.8423153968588));
#1601=CARTESIAN_POINT('',(41.3615434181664,21.1201964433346,25.923413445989));
#1602=CARTESIAN_POINT('',(41.6087481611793,21.0220250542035,25.9533109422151));
#1603=CARTESIAN_POINT('',(42.1049750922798,20.8218139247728,25.9925713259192));
#1604=CARTESIAN_POINT('',(42.3539990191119,20.7197539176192,26.0018053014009));
#1605=CARTESIAN_POINT('',(42.8532574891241,20.5191051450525,25.9994058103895));
#1606=CARTESIAN_POINT('',(43.103491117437,20.4205141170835,25.9877862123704));
#1607=CARTESIAN_POINT('',(43.4911612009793,20.2781905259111,25.9531754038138));
#1608=CARTESIAN_POINT('',(43.6276717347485,20.2300431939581,25.9378480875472));
#1609=CARTESIAN_POINT('',(43.901683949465,20.1392579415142,25.9005847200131));
#1610=CARTESIAN_POINT('',(44.0391857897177,20.096620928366,25.8786475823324));
#1611=CARTESIAN_POINT('',(44.3142265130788,20.0192528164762,25.8280504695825));
#1612=CARTESIAN_POINT('',(44.4517594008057,19.9844723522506,25.7994349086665));
#1613=CARTESIAN_POINT('',(44.7272766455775,19.9247616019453,25.7351902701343));
#1614=CARTESIAN_POINT('',(44.8652606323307,19.8998246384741,25.6995659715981));
#1615=CARTESIAN_POINT('',(45.1434941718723,19.8614808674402,25.6204926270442));
#1616=CARTESIAN_POINT('',(45.283737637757,19.8482992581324,25.57690926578));
#1617=CARTESIAN_POINT('',(45.5624418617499,19.835618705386,25.4826498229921));
#1618=CARTESIAN_POINT('',(45.700902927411,19.8361173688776,25.4319749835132));
#1619=CARTESIAN_POINT('',(45.974868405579,19.8507576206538,25.3239624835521));
#1620=CARTESIAN_POINT('',(46.1103639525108,19.8649355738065,25.2666074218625));
#1621=CARTESIAN_POINT('',(46.3768331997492,19.9055546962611,25.146049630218));
#1622=CARTESIAN_POINT('',(46.5078052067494,19.9320004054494,25.0828447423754));
#1623=CARTESIAN_POINT('',(46.8058364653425,20.0050243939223,24.9300782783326));
#1624=CARTESIAN_POINT('',(46.9709696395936,20.0553411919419,24.8385732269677));
#1625=CARTESIAN_POINT('',(47.2921126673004,20.1679611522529,24.6473685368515));
#1626=CARTESIAN_POINT('',(47.448116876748,20.2302716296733,24.5476639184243));
#1627=CARTESIAN_POINT('',(47.7523487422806,20.3624764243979,24.3398687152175));
#1628=CARTESIAN_POINT('',(47.9005313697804,20.4324087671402,24.2317369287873));
#1629=CARTESIAN_POINT('',(48.1888790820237,20.5757993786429,24.0075456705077));
#1630=CARTESIAN_POINT('',(48.3290458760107,20.6492568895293,23.8914879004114));
#1631=CARTESIAN_POINT('',(48.6202071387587,20.806610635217,23.6350806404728));
#1632=CARTESIAN_POINT('',(48.7701310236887,20.8905850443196,23.4935611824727));
#1633=CARTESIAN_POINT('',(49.0606554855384,21.0556021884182,23.1995951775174));
#1634=CARTESIAN_POINT('',(49.2012549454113,21.1366445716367,23.0471473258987));
#1635=CARTESIAN_POINT('',(49.4719906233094,21.2919846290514,22.7320725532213));
#1636=CARTESIAN_POINT('',(49.6021930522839,21.366325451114,22.5695241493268));
#1637=CARTESIAN_POINT('',(49.8526221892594,21.5057597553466,22.2331121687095));
#1638=CARTESIAN_POINT('',(49.972850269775,21.5708545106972,22.0592501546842));
#1639=CARTESIAN_POINT('',(50.1798633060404,21.6770136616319,21.7355454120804));
#1640=CARTESIAN_POINT('',(50.2685858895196,21.7202874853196,21.587669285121));
#1641=CARTESIAN_POINT('',(50.4382462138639,21.7969547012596,21.2851337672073));
#1642=CARTESIAN_POINT('',(50.5191888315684,21.830354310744,21.1304787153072));
#1643=CARTESIAN_POINT('',(50.6736591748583,21.8858346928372,20.8127282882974));
#1644=CARTESIAN_POINT('',(50.7470677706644,21.9077511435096,20.6495452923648));
#1645=CARTESIAN_POINT('',(50.884503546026,21.9376591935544,20.3176318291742));
#1646=CARTESIAN_POINT('',(50.9485094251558,21.9456196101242,20.1488897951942));
#1647=CARTESIAN_POINT('',(51.0073180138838,21.9455999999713,19.9781705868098));
#1648=B_SPLINE_CURVE_WITH_KNOTS('',3,(#1588,#1589,#1590,#1591,#1592,#1593,#1594,#1595,#1596,
#1597,#1598,#1599,#1600,#1601,#1602,#1603,#1604,#1605,#1606,#1607,#1608,#1609,#1610,#1611,#1612,
#1613,#1614,#1615,#1616,#1617,#1618,#1619,#1620,#1621,#1622,#1623,#1624,#1625,#1626,#1627,#1628,
#1629,#1630,#1631,#1632,#1633,#1634,#1635,#1636,#1637,#1638,#1639,#1640,#1641,#1642,#1643,#1644,
#1645,#1646,#1647),.UNSPECIFIED.,.F.,.F.,(4,2,2,2,2,2,2,2,2,2,2,2,2,2,2,2,2,2,2,2,2,2,2,2,2,2,2,
2,2,4),(0.,0.308734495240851,0.617340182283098,1.23263991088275,1.83914644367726,
2.44613883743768,3.24791785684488,4.05002806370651,4.85712854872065,5.66369247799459,
6.10017914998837,6.53673760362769,6.97047158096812,7.40391082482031,7.84548543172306,
8.28698279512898,8.72965707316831,9.17249530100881,9.75761915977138,10.3431010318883,
10.931650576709,11.5200741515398,12.1874488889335,12.8549034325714,13.5176969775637,
14.1803991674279,14.7132823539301,15.2458292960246,15.7858019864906,16.3269796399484),.UNSPECIFIED.);
#1649=CARTESIAN_POINT('',(38.157341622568,21.941509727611,24.840213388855));
#1650=VERTEX_POINT('',#1649);
#1651=EDGE_CURVE('E422',#1650,#160,#1648,.T.);
#1652=ORIENTED_EDGE('',*,*,#1651,.F.);
#1653=CARTESIAN_POINT('',(35.784229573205,21.9456016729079,26.1180782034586));
#1654=CARTESIAN_POINT('',(35.8572652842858,21.9455982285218,26.100488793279));
#1655=CARTESIAN_POINT('',(35.9299162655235,21.9453721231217,26.0813451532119));
#1656=CARTESIAN_POINT('',(36.0743352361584,21.9446252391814,26.0399819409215));
#1657=CARTESIAN_POINT('',(36.1461032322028,21.9441044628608,26.0177623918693));
#1658=CARTESIAN_POINT('',(36.3599280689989,21.9423259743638,25.9465335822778));
#1659=CARTESIAN_POINT('',(36.5004913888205,21.94085216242,25.8929576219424));
#1660=CARTESIAN_POINT('',(36.7735984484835,21.9382667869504,25.7753031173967));
#1661=CARTESIAN_POINT('',(36.9062491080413,21.9371481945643,25.7114718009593));
#1662=CARTESIAN_POINT('',(37.1657173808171,21.9357249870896,25.5730094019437));
#1663=CARTESIAN_POINT('',(37.2925375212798,21.9354200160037,25.4983830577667));
#1664=CARTESIAN_POINT('',(37.5470935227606,21.9357608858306,25.3339298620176));
#1665=CARTESIAN_POINT('',(37.674411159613,21.9364660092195,25.2434525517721));
#1666=CARTESIAN_POINT('',(37.8596888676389,21.9380764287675,25.0990460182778));
#1667=CARTESIAN_POINT('',(37.9208344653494,21.9387106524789,25.0491483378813));
#1668=CARTESIAN_POINT('',(38.0408317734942,21.9400677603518,24.9466693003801));
#1669=CARTESIAN_POINT('',(38.0996835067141,21.9407906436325,24.8940879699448));
#1670=CARTESIAN_POINT('',(38.1573375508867,21.9415089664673,24.8402090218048));
#1671=B_SPLINE_CURVE_WITH_KNOTS('',3,(#1653,#1654,#1655,#1656,#1657,#1658,#1659,#1660,#1661,
#1662,#1663,#1664,#1665,#1666,#1667,#1668,#1669,#1670),.UNSPECIFIED.,.F.,.F.,(4,2,2,2,2,2,2,2,
4),(0.,0.225334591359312,0.450667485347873,0.901377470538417,1.34251498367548,1.78345944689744,
2.25136763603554,2.48807095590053,2.72477192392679),.UNSPECIFIED.);
#1672=EDGE_CURVE('E144',#142,#1650,#1671,.T.);
#1673=ORIENTED_EDGE('',*,*,#1672,.F.);
#1674=EDGE_LOOP('',(#1509,#1578,#1585,#1586,#1587,#1652,#1673));
#1675=FACE_BOUND('',#1674,.T.);
#1676=ADVANCED_FACE('F398',(#1675),#1508,.T.);
#1677=CARTESIAN_POINT('',(27.9144720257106,17.2908553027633,42.0285427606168));
#1678=CARTESIAN_POINT('',(27.8976921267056,18.1174045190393,42.0202673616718));
#1679=CARTESIAN_POINT('',(27.6822696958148,18.9453041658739,41.9140129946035));
#1680=CARTESIAN_POINT('',(26.9163831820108,20.3489817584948,41.536437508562));
#1681=CARTESIAN_POINT('',(26.38139852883,20.9271552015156,41.2727594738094));
#1682=CARTESIAN_POINT('',(25.3562800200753,21.5750568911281,40.767809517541));
#1683=CARTESIAN_POINT('',(24.9302216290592,21.7523565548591,40.5580031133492));
#1684=CARTESIAN_POINT('',(24.2072032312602,21.9144236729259,40.2020807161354));
#1685=CARTESIAN_POINT('',(23.9235354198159,21.9456,40.0624658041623));
#1686=CARTESIAN_POINT('',(23.6425655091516,21.9456,39.9242044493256));
#1687=CARTESIAN_POINT('',(27.820437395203,17.2907462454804,42.2103528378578));
#1688=CARTESIAN_POINT('',(27.8036870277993,18.1164593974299,42.2021076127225));
#1689=CARTESIAN_POINT('',(27.5886692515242,18.9435582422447,42.0962558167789));
#1690=CARTESIAN_POINT('',(26.8238736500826,20.3465197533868,41.7199042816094));
#1691=CARTESIAN_POINT('',(26.28953171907,20.9247598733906,41.4570099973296));
#1692=CARTESIAN_POINT('',(25.2650799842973,21.5733563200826,40.9532271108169));
#1693=CARTESIAN_POINT('',(24.8391852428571,21.7510494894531,40.7438385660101));
#1694=CARTESIAN_POINT('',(24.1162196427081,21.9138398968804,40.3884926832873));
#1695=CARTESIAN_POINT('',(23.8325207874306,21.9453121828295,40.2490734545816));
#1696=CARTESIAN_POINT('',(23.5514705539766,21.9456,40.1109767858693));
#1697=CARTESIAN_POINT('',(27.6533398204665,17.2887623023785,42.3530356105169));
#1698=CARTESIAN_POINT('',(27.636897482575,18.0992576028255,42.3449651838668));
#1699=CARTESIAN_POINT('',(27.4258445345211,18.9111297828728,42.2413661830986));
#1700=CARTESIAN_POINT('',(26.6750048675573,20.2885586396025,41.8729052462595));
#1701=CARTESIAN_POINT('',(26.1503634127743,20.8564418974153,41.6154819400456));
#1702=CARTESIAN_POINT('',(25.1442696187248,21.4937087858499,41.1219898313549));
#1703=CARTESIAN_POINT('',(24.7259585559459,21.6683922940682,40.9168396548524));
#1704=CARTESIAN_POINT('',(24.0157701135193,21.8285941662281,40.5686096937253));
#1705=CARTESIAN_POINT('',(23.7370629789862,21.8596386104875,40.4319646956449));
#1706=CARTESIAN_POINT('',(23.4609365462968,21.8600551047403,40.2965990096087));
#1707=CARTESIAN_POINT('',(27.2647913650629,17.2821342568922,42.4817829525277));
#1708=CARTESIAN_POINT('',(27.2493641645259,18.0417882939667,42.4742457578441));
#1709=CARTESIAN_POINT('',(27.0513365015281,18.8027289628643,42.3774945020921));
#1710=CARTESIAN_POINT('',(26.3469032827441,20.0936800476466,42.0333511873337));
#1711=CARTESIAN_POINT('',(25.8547111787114,20.6258727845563,41.7929045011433));
#1712=CARTESIAN_POINT('',(24.9109532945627,21.2230247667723,41.3318978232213));
#1713=CARTESIAN_POINT('',(24.518581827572,21.3866913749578,41.1402402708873));
#1714=CARTESIAN_POINT('',(23.8524749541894,21.5367526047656,40.8148897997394));
#1715=CARTESIAN_POINT('',(23.5910770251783,21.5658160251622,40.6872172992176));
#1716=CARTESIAN_POINT('',(23.3321088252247,21.5661769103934,40.5607349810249));
#1717=CARTESIAN_POINT('',(27.0455948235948,17.2775286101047,42.4671005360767));
#1718=CARTESIAN_POINT('',(27.0308694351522,18.0018542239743,42.4599184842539));
#1719=CARTESIAN_POINT('',(26.8418348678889,18.7273863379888,42.3677201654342));
#1720=CARTESIAN_POINT('',(26.1696041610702,19.9579092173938,42.039851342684));
#1721=CARTESIAN_POINT('',(25.6999847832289,20.4649894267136,41.8108026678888));
#1722=CARTESIAN_POINT('',(24.7998533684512,21.0336180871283,41.3717792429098));
#1723=CARTESIAN_POINT('',(24.4256889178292,21.1893538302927,41.1892870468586));
#1724=CARTESIAN_POINT('',(23.7906281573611,21.3319411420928,40.8795472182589));
#1725=CARTESIAN_POINT('',(23.5414450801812,21.359470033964,40.7580125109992));
#1726=CARTESIAN_POINT('',(23.2946084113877,21.3596532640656,40.6376222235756));
#1727=CARTESIAN_POINT('',(26.8616690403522,17.2728960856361,42.3773939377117));
#1728=CARTESIAN_POINT('',(26.8476543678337,17.9616870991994,42.3705585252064));
#1729=CARTESIAN_POINT('',(26.667727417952,18.6516034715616,42.2828022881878));
#1730=CARTESIAN_POINT('',(26.0281034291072,19.8213347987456,41.9708368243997));
#1731=CARTESIAN_POINT('',(25.581338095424,20.303146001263,41.7529348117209));
#1732=CARTESIAN_POINT('',(24.7253677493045,20.8430640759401,41.3354501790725));
#1733=CARTESIAN_POINT('',(24.3696316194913,20.9908137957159,41.1619460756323));
#1734=CARTESIAN_POINT('',(23.7659908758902,21.1258697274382,40.8675308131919));
#1735=CARTESIAN_POINT('',(23.5291689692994,21.15185,40.7520250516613));
#1736=CARTESIAN_POINT('',(23.2946084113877,21.15185,40.6376222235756));
#1737=B_SPLINE_SURFACE_WITH_KNOTS('',3,3,((#1677,#1678,#1679,#1680,#1681,#1682,#1683,#1684,
#1685,#1686),(#1687,#1688,#1689,#1690,#1691,#1692,#1693,#1694,#1695,#1696),(#1697,#1698,#1699,
#1700,#1701,#1702,#1703,#1704,#1705,#1706),(#1707,#1708,#1709,#1710,#1711,#1712,#1713,#1714,
#1715,#1716),(#1717,#1718,#1719,#1720,#1721,#1722,#1723,#1724,#1725,#1726),(#1727,#1728,#1729,
#1730,#1731,#1732,#1733,#1734,#1735,#1736)),.UNSPECIFIED.,.F.,.F.,.F.,(4,2,4),(4,2,2,2,4),(0.,
0.5,1.),(-0.610675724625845,-0.403985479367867,-0.203558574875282,-0.078291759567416,0.),.UNSPECIFIED.);
#1738=CARTESIAN_POINT('',(23.2946084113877,21.15185,40.6376222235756));
#1739=CARTESIAN_POINT('',(23.5291689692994,21.15185,40.7520250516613));
#1740=CARTESIAN_POINT('',(23.7659908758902,21.1258697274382,40.8675308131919));
#1741=CARTESIAN_POINT('',(24.3696316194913,20.9908137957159,41.1619460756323));
#1742=CARTESIAN_POINT('',(24.7253677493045,20.8430640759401,41.3354501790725));
#1743=CARTESIAN_POINT('',(25.581338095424,20.303146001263,41.7529348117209));
#1744=CARTESIAN_POINT('',(26.0281034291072,19.8213347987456,41.9708368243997));
#1745=CARTESIAN_POINT('',(26.667727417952,18.6516034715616,42.2828022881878));
#1746=CARTESIAN_POINT('',(26.8476543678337,17.9616870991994,42.3705585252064));
#1747=CARTESIAN_POINT('',(26.8616690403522,17.2728960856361,42.3773939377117));
#1748=B_SPLINE_CURVE_WITH_KNOTS('',3,(#1738,#1739,#1740,#1741,#1742,#1743,#1744,#1745,#1746,
#1747),.UNSPECIFIED.,.F.,.F.,(4,2,2,2,4),(-0.610675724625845,-0.532383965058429,
-0.407117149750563,-0.206690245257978,0.),.UNSPECIFIED.);
#1749=CARTESIAN_POINT('',(23.294608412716,21.15185,40.6376222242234));
#1750=VERTEX_POINT('',#1749);
#1751=EDGE_CURVE('E134',#1750,#1041,#1748,.T.);
#1752=CARTESIAN_POINT('',(23.6425655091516,21.9456,39.9242044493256));
#1753=CARTESIAN_POINT('',(23.6368737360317,21.9456001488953,39.9358743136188));
#1754=CARTESIAN_POINT('',(23.6311822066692,21.9452660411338,39.9475436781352));
#1755=CARTESIAN_POINT('',(23.6198160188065,21.9439410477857,39.9708478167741));
#1756=CARTESIAN_POINT('',(23.6141413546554,21.9429504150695,39.9824826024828));
#1757=CARTESIAN_POINT('',(23.6028215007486,21.9403242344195,40.0056917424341));
#1758=CARTESIAN_POINT('',(23.5971763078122,21.9386887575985,40.0172661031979));
#1759=CARTESIAN_POINT('',(23.5859278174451,21.934784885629,40.0403289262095));
#1760=CARTESIAN_POINT('',(23.5803245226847,21.9325164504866,40.0518173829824));
#1761=CARTESIAN_POINT('',(23.5691722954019,21.9273585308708,40.0746828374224));
#1762=CARTESIAN_POINT('',(23.5636233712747,21.9244689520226,40.0860598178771));
#1763=CARTESIAN_POINT('',(23.5525923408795,21.9180805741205,40.1086767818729));
#1764=CARTESIAN_POINT('',(23.5471102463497,21.9145816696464,40.1199167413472));
#1765=CARTESIAN_POINT('',(23.5362253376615,21.9069864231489,40.1422341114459));
#1766=CARTESIAN_POINT('',(23.530822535,21.9028899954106,40.153311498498));
#1767=CARTESIAN_POINT('',(23.5201086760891,21.8941114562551,40.1752781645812));
#1768=CARTESIAN_POINT('',(23.514797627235,21.8894292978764,40.1861674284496));
#1769=CARTESIAN_POINT('',(23.5042797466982,21.8794910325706,40.2077322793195));
#1770=CARTESIAN_POINT('',(23.4990729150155,21.8742349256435,40.218407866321));
#1771=CARTESIAN_POINT('',(23.4887759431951,21.8631604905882,40.239519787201));
#1772=CARTESIAN_POINT('',(23.4836857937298,21.857342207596,40.2499561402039));
#1773=CARTESIAN_POINT('',(23.4736346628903,21.8451551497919,40.2705640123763));
#1774=CARTESIAN_POINT('',(23.4686736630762,21.8387864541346,40.2807355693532));
#1775=CARTESIAN_POINT('',(23.4588933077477,21.825510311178,40.3007882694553));
#1776=CARTESIAN_POINT('',(23.4540739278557,21.8186029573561,40.3106694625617));
#1777=CARTESIAN_POINT('',(23.4445892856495,21.8042612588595,40.3301158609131));
#1778=CARTESIAN_POINT('',(23.4399240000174,21.7968269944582,40.3396811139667));
#1779=CARTESIAN_POINT('',(23.4307600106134,21.7814432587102,40.358470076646));
#1780=CARTESIAN_POINT('',(23.4262612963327,21.7734938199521,40.3676938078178));
#1781=CARTESIAN_POINT('',(23.4174429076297,21.7570915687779,40.3857741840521));
#1782=CARTESIAN_POINT('',(23.4131232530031,21.7486387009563,40.3946307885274));
#1783=CARTESIAN_POINT('',(23.4046754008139,21.7312414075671,40.411951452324));
#1784=CARTESIAN_POINT('',(23.4005472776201,21.7222967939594,40.4204153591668));
#1785=CARTESIAN_POINT('',(23.3924980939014,21.7039352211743,40.4369186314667));
#1786=CARTESIAN_POINT('',(23.3885770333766,21.694518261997,40.4449579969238));
#1787=CARTESIAN_POINT('',(23.3809505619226,21.6752472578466,40.4605945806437));
#1788=CARTESIAN_POINT('',(23.377245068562,21.6653933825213,40.4681919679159));
#1789=CARTESIAN_POINT('',(23.3700547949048,21.6452771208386,40.4829342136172));
#1790=CARTESIAN_POINT('',(23.3665699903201,21.6350147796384,40.4900791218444));
#1791=CARTESIAN_POINT('',(23.3598262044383,21.6141101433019,40.5039059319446));
#1792=CARTESIAN_POINT('',(23.3565672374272,21.6034678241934,40.510587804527));
#1793=CARTESIAN_POINT('',(23.3502802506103,21.5818317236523,40.5234780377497));
#1794=CARTESIAN_POINT('',(23.3472522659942,21.5708378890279,40.5296863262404));
#1795=CARTESIAN_POINT('',(23.3414323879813,21.5485272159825,40.5416188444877));
#1796=CARTESIAN_POINT('',(23.3386405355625,21.5372103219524,40.5473429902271));
#1797=CARTESIAN_POINT('',(23.3332980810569,21.5142819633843,40.5582966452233));
#1798=CARTESIAN_POINT('',(23.3307475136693,21.5026704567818,40.5635260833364));
#1799=CARTESIAN_POINT('',(23.3258928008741,21.4791812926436,40.5734797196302));
#1800=CARTESIAN_POINT('',(23.3235886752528,21.4673036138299,40.578203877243));
#1801=CARTESIAN_POINT('',(23.3192320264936,21.443310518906,40.5871363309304));
#1802=CARTESIAN_POINT('',(23.3171795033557,21.4311951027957,40.591344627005));
#1803=CARTESIAN_POINT('',(23.313331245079,21.4067549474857,40.5992347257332));
#1804=CARTESIAN_POINT('',(23.3115354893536,21.3944302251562,40.6029165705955));
#1805=CARTESIAN_POINT('',(23.3082059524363,21.3695998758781,40.6097431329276));
#1806=CARTESIAN_POINT('',(23.3066721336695,21.3570942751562,40.6128879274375));
#1807=CARTESIAN_POINT('',(23.3038716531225,21.3319305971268,40.6186297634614));
#1808=CARTESIAN_POINT('',(23.302604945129,21.3192725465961,40.6212268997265));
#1809=CARTESIAN_POINT('',(23.300343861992,21.2938323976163,40.6258628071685));
#1810=CARTESIAN_POINT('',(23.2993494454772,21.2810503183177,40.6279016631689));
#1811=CARTESIAN_POINT('',(23.297638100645,21.2553905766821,40.6314104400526));
#1812=CARTESIAN_POINT('',(23.2969211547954,21.2425129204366,40.6328803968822));
#1813=CARTESIAN_POINT('',(23.2957699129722,21.21669038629,40.6352407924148));
#1814=CARTESIAN_POINT('',(23.2953356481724,21.2037455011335,40.6361311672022));
#1815=CARTESIAN_POINT('',(23.2947548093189,21.1778172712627,40.6373220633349));
#1816=CARTESIAN_POINT('',(23.2946083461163,21.1648339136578,40.6376223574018));
#1817=CARTESIAN_POINT('',(23.2946084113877,21.15185,40.6376222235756));
#1818=B_SPLINE_CURVE_WITH_KNOTS('',3,(#1752,#1753,#1754,#1755,#1756,#1757,#1758,#1759,#1760,
#1761,#1762,#1763,#1764,#1765,#1766,#1767,#1768,#1769,#1770,#1771,#1772,#1773,#1774,#1775,#1776,
#1777,#1778,#1779,#1780,#1781,#1782,#1783,#1784,#1785,#1786,#1787,#1788,#1789,#1790,#1791,#1792,
#1793,#1794,#1795,#1796,#1797,#1798,#1799,#1800,#1801,#1802,#1803,#1804,#1805,#1806,#1807,#1808,
#1809,#1810,#1811,#1812,#1813,#1814,#1815,#1816,#1817),.UNSPECIFIED.,.F.,.F.,(4,2,2,2,2,2,2,2,2,
2,2,2,2,2,2,2,2,2,2,2,2,2,2,2,2,2,2,2,2,2,2,2,4),(0.,0.0389466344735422,0.0778782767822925,
0.116805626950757,0.15573543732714,0.194671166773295,0.233613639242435,0.272561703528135,
0.31151289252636,0.35046408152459,0.389412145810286,0.428354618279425,0.467290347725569,
0.506220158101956,0.545147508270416,0.584079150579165,0.623025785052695,0.661972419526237,
0.700904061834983,0.739831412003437,0.778761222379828,0.817696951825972,0.856639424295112,
0.895587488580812,0.934538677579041,0.973489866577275,1.01243793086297,1.05138040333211,
1.09031613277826,1.12924594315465,1.16817329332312,1.20710493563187,1.24605157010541),.UNSPECIFIED.);
#1819=EDGE_CURVE('E149',#1750,#133,#1818,.F.);
#1820=ORIENTED_EDGE('',*,*,#1751,.T.);
#1821=ORIENTED_EDGE('',*,*,#1042,.F.);
#1822=ORIENTED_EDGE('',*,*,#1577,.T.);
#1823=ORIENTED_EDGE('',*,*,#1819,.F.);
#1824=EDGE_LOOP('',(#1820,#1821,#1822,#1823));
#1825=FACE_BOUND('',#1824,.T.);
#1826=ADVANCED_FACE('F151',(#1825),#1737,.F.);
#1827=CARTESIAN_POINT('',(27.0143982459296,21.151850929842,42.4518849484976));
#1828=DIRECTION('',(0.438371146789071,0.,-0.898794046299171));
#1829=DIRECTION('',(0.898794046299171,0.,0.438371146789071));
#1830=AXIS2_PLACEMENT_3D('',#1827,#1828,#1829);
#1831=PLANE('',#1830);
#1832=DIRECTION('',(-0.89879404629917,0.,-0.438371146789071));
#1833=VECTOR('',#1832,1.);
#1834=CARTESIAN_POINT('',(23.2946084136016,21.15185,40.6376222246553));
#1835=LINE('',#1834,#1833);
#1836=EDGE_CURVE('E139',#376,#1750,#1835,.F.);
#1837=ORIENTED_EDGE('',*,*,#1836,.F.);
#1838=ORIENTED_EDGE('',*,*,#377,.T.);
#1839=ORIENTED_EDGE('',*,*,#1047,.F.);
#1840=ORIENTED_EDGE('',*,*,#1751,.F.);
#1841=EDGE_LOOP('',(#1837,#1838,#1839,#1840));
#1842=FACE_BOUND('',#1841,.T.);
#1843=ADVANCED_FACE('F137',(#1842),#1831,.F.);
#1844=CARTESIAN_POINT('',(23.6425655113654,21.15185,39.9242044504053));
#1845=DIRECTION('',(-0.89879404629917,0.,-0.438371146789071));
#1846=DIRECTION('',(0.438371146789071,0.,-0.89879404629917));
#1847=AXIS2_PLACEMENT_3D('',#1844,#1845,#1846);
#1848=CYLINDRICAL_SURFACE('',#1847,0.79375);
#1849=ORIENTED_EDGE('',*,*,#1836,.T.);
#1850=ORIENTED_EDGE('',*,*,#1819,.T.);
#1851=ORIENTED_EDGE('',*,*,#134,.T.);
#1852=ORIENTED_EDGE('',*,*,#406,.T.);
#1853=EDGE_LOOP('',(#1849,#1850,#1851,#1852));
#1854=FACE_BOUND('',#1853,.T.);
#1855=ADVANCED_FACE('F160',(#1854),#1848,.T.);
#1856=CARTESIAN_POINT('',(57.15,-98.7044000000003,57.15));
#1857=DIRECTION('',(0.,1.,0.));
#1858=DIRECTION('',(0.224951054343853,0.,-0.974370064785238));
#1859=AXIS2_PLACEMENT_3D('',#1856,#1857,#1858);
#1860=CONICAL_SURFACE('',#1859,30.2894999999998,0.0226277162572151);
#1861=ORIENTED_EDGE('',*,*,#1187,.F.);
#1862=ORIENTED_EDGE('',*,*,#1584,.T.);
#1863=ORIENTED_EDGE('',*,*,#1024,.F.);
#1864=ORIENTED_EDGE('',*,*,#756,.F.);
#1865=EDGE_LOOP('',(#1861,#1862,#1863,#1864));
#1866=FACE_BOUND('',#1865,.T.);
#1867=ADVANCED_FACE('F1032',(#1866),#1860,.F.);
#1868=CARTESIAN_POINT('',(42.5607112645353,21.9456,17.0662586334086));
#1869=DIRECTION('',(0.,1.,0.));
#1870=DIRECTION('',(0.224951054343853,0.,-0.974370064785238));
#1871=AXIS2_PLACEMENT_3D('',#1868,#1869,#1870);
#1872=CYLINDRICAL_SURFACE('',#1871,8.93445000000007);
#1873=ORIENTED_EDGE('',*,*,#161,.T.);
#1874=DIRECTION('',(0.,1.,0.));
#1875=VECTOR('',#1874,1.);
#1876=CARTESIAN_POINT('',(33.7237415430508,21.9456,15.7500660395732));
#1877=LINE('',#1876,#1875);
#1878=CARTESIAN_POINT('',(33.7237415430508,25.4,15.7500660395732));
#1879=VERTEX_POINT('',#1878);
#1880=EDGE_CURVE('E181',#1879,#151,#1877,.F.);
#1881=ORIENTED_EDGE('',*,*,#1880,.F.);
#1882=CARTESIAN_POINT('',(42.5607112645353,25.4,17.0662586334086));
#1883=DIRECTION('',(0.,1.,0.));
#1884=DIRECTION('',(0.224951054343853,0.,-0.974370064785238));
#1885=AXIS2_PLACEMENT_3D('',#1882,#1883,#1884);
#1886=CIRCLE('',#1885,8.93445000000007);
#1887=CARTESIAN_POINT('',(38.1573207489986,25.4,24.8402247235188));
#1888=VERTEX_POINT('',#1887);
#1889=EDGE_CURVE('E70',#1879,#1888,#1886,.F.);
#1890=ORIENTED_EDGE('',*,*,#1889,.T.);
#1891=DIRECTION('',(0.,1.,0.));
#1892=VECTOR('',#1891,1.);
#1893=CARTESIAN_POINT('',(38.1573207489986,21.941509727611,24.8402247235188));
#1894=LINE('',#1893,#1892);
#1895=EDGE_CURVE('E188',#1650,#1888,#1894,.T.);
#1896=ORIENTED_EDGE('',*,*,#1895,.F.);
#1897=ORIENTED_EDGE('',*,*,#1651,.T.);
#1898=EDGE_LOOP('',(#1873,#1881,#1890,#1896,#1897));
#1899=FACE_BOUND('',#1898,.T.);
#1900=ADVANCED_FACE('F1041',(#1899),#1872,.T.);
#1901=CARTESIAN_POINT('',(34.5456490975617,21.9338471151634,20.9754767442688));
#1902=DIRECTION('',(0.,1.,0.));
#1903=DIRECTION('',(0.224951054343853,0.,-0.974370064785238));
#1904=AXIS2_PLACEMENT_3D('',#1901,#1902,#1903);
#1905=CYLINDRICAL_SURFACE('',#1904,5.289654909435);
#1906=ORIENTED_EDGE('',*,*,#1672,.T.);
#1907=ORIENTED_EDGE('',*,*,#1895,.T.);
#1908=CARTESIAN_POINT('',(34.5456490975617,25.4,20.9754767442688));
#1909=DIRECTION('',(0.,1.,0.));
#1910=DIRECTION('',(0.224951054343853,0.,-0.974370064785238));
#1911=AXIS2_PLACEMENT_3D('',#1908,#1909,#1910);
#1912=CIRCLE('',#1911,5.289654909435);
#1913=EDGE_CURVE('E190',#1888,#1879,#1912,.F.);
#1914=ORIENTED_EDGE('',*,*,#1913,.T.);
#1915=ORIENTED_EDGE('',*,*,#1880,.T.);
#1916=ORIENTED_EDGE('',*,*,#152,.T.);
#1917=EDGE_LOOP('',(#1906,#1907,#1914,#1915,#1916));
#1918=FACE_BOUND('',#1917,.T.);
#1919=ADVANCED_FACE('F1051',(#1918),#1905,.T.);
#1920=CARTESIAN_POINT('',(57.15,25.4,57.15));
#1921=DIRECTION('',(0.,-1.,0.));
#1922=DIRECTION('',(-0.224951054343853,0.,0.974370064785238));
#1923=AXIS2_PLACEMENT_3D('',#1920,#1921,#1922);
#1924=PLANE('',#1923);
#1925=ORIENTED_EDGE('',*,*,#1889,.F.);
#1926=ORIENTED_EDGE('',*,*,#1913,.F.);
#1927=EDGE_LOOP('',(#1925,#1926));
#1928=FACE_BOUND('',#1927,.T.);
#1929=ADVANCED_FACE('F622',(#1928),#1924,.F.);
#1930=CARTESIAN_POINT('',(57.15,9.76659464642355,10.4436921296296));
#1931=DIRECTION('',(-1.,0.,0.));
#1932=DIRECTION('',(0.,0.,-1.));
#1933=AXIS2_PLACEMENT_3D('',#1930,#1931,#1932);
#1934=PLANE('',#1933);
#1935=ORIENTED_EDGE('',*,*,#666,.T.);
#1936=ORIENTED_EDGE('',*,*,#1349,.F.);
#1937=ORIENTED_EDGE('',*,*,#1496,.T.);
#1938=ORIENTED_EDGE('',*,*,#1160,.F.);
#1939=EDGE_LOOP('',(#1935,#1936,#1937,#1938));
#1940=FACE_BOUND('',#1939,.T.);
#1941=ADVANCED_FACE('F611',(#1940),#1934,.F.);
#1942=CARTESIAN_POINT('',(57.15,214.474511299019,57.15));
#1943=DIRECTION('',(0.974370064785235,0.,0.224951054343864));
#1944=DIRECTION('',(0.224951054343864,0.,-0.974370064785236));
#1945=AXIS2_PLACEMENT_3D('',#1942,#1943,#1944);
#1946=PLANE('',#1945);
#1947=ORIENTED_EDGE('',*,*,#748,.F.);
#1948=DIRECTION('',(0.,-1.,0.));
#1949=VECTOR('',#1948,1.);
#1950=CARTESIAN_POINT('',(57.15,214.474511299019,57.15));
#1951=LINE('',#1950,#1949);
#1952=EDGE_CURVE('E809',#741,#903,#1951,.T.);
#1953=ORIENTED_EDGE('',*,*,#1952,.T.);
#1954=ORIENTED_EDGE('',*,*,#904,.F.);
#1955=ORIENTED_EDGE('',*,*,#872,.F.);
#1956=ORIENTED_EDGE('',*,*,#839,.T.);
#1957=ORIENTED_EDGE('',*,*,#807,.T.);
#1958=ORIENTED_EDGE('',*,*,#774,.T.);
#1959=ORIENTED_EDGE('',*,*,#70,.T.);
#1960=ORIENTED_EDGE('',*,*,#240,.F.);
#1961=ORIENTED_EDGE('',*,*,#261,.T.);
#1962=ORIENTED_EDGE('',*,*,#247,.F.);
#1963=ORIENTED_EDGE('',*,*,#208,.T.);
#1964=ORIENTED_EDGE('',*,*,#719,.F.);
#1965=ORIENTED_EDGE('',*,*,#544,.T.);
#1966=EDGE_LOOP('',(#1947,#1953,#1954,#1955,#1956,#1957,#1958,#1959,#1960,#1961,#1962,#1963,
#1964,#1965));
#1967=FACE_BOUND('',#1966,.T.);
#1968=ADVANCED_FACE('F621',(#1967),#1946,.T.);
#1969=CARTESIAN_POINT('',(57.15,214.474511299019,57.15));
#1970=DIRECTION('',(-0.224951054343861,0.,0.974370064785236));
#1971=DIRECTION('',(0.974370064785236,0.,0.224951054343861));
#1972=AXIS2_PLACEMENT_3D('',#1969,#1970,#1971);
#1973=PLANE('',#1972);
#1974=ORIENTED_EDGE('',*,*,#742,.F.);
#1975=ORIENTED_EDGE('',*,*,#327,.T.);
#1976=ORIENTED_EDGE('',*,*,#504,.F.);
#1977=ORIENTED_EDGE('',*,*,#100,.T.);
#1978=ORIENTED_EDGE('',*,*,#287,.F.);
#1979=ORIENTED_EDGE('',*,*,#308,.T.);
#1980=ORIENTED_EDGE('',*,*,#294,.F.);
#1981=ORIENTED_EDGE('',*,*,#87,.T.);
#1982=ORIENTED_EDGE('',*,*,#790,.T.);
#1983=ORIENTED_EDGE('',*,*,#822,.T.);
#1984=ORIENTED_EDGE('',*,*,#854,.T.);
#1985=ORIENTED_EDGE('',*,*,#887,.F.);
#1986=ORIENTED_EDGE('',*,*,#910,.F.);
#1987=ORIENTED_EDGE('',*,*,#1952,.F.);
#1988=EDGE_LOOP('',(#1974,#1975,#1976,#1977,#1978,#1979,#1980,#1981,#1982,#1983,#1984,#1985,
#1986,#1987));
#1989=FACE_BOUND('',#1988,.T.);
#1990=ADVANCED_FACE('F812',(#1989),#1973,.T.);
#1991=CLOSED_SHELL('',(#219,#251,#266,#298,#313,#493,#530,#708,#730,#761,#795,#827,#859,#891,
#914,#1054,#1194,#1226,#1251,#1277,#1294,#1306,#1317,#1328,#1355,#1503,#1676,#1826,#1843,#1855,
#1867,#1900,#1919,#1929,#1941,#1968,#1990));
#1992=MANIFOLD_SOLID_BREP('B2',#1991);
#1993=ADVANCED_BREP_SHAPE_REPRESENTATION('',(#18,#1992),#14);
#1994=SHAPE_DEFINITION_REPRESENTATION(#9,#1993);
ENDSEC;
END-ISO-10303-21;
